VERSION 5.8 ;
BUSBITCHARS "[]" ;
DIVIDERCHAR "/" ;
UNITS
    DATABASE MICRONS 1000 ;
END UNITS

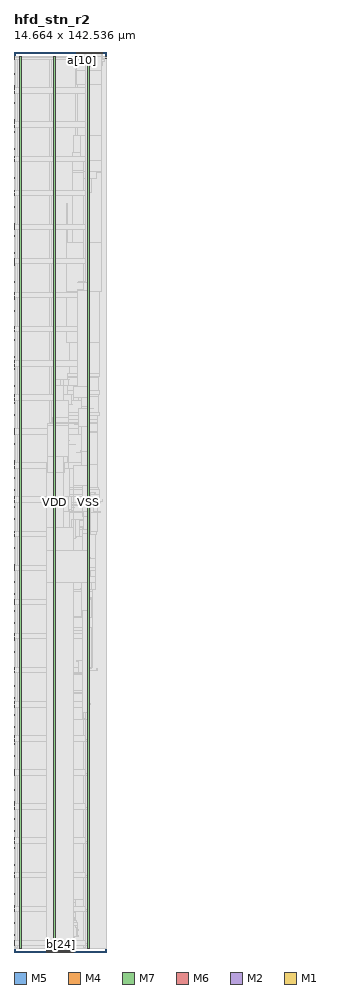
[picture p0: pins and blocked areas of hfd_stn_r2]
MACRO hfd_stn_r2
  FOREIGN hfd_stn_r2 0 0 ;
  CLASS BLOCK ;
  SIZE 14.664 BY 142.536 ;
  PIN a[0]
    DIRECTION INPUT ;
    USE SIGNAL ;
    PORT
      LAYER M5 ;
        RECT  9.84 142.344 9.864 142.536 ;
    END
  END a[0]
  PIN a[10]
    DIRECTION INPUT ;
    USE SIGNAL ;
    PORT
      LAYER M5 ;
        RECT  10.8 142.344 10.824 142.536 ;
    END
  END a[10]
  PIN a[11]
    DIRECTION INPUT ;
    USE SIGNAL ;
    PORT
      LAYER M5 ;
        RECT  10.896 142.344 10.92 142.536 ;
    END
  END a[11]
  PIN a[12]
    DIRECTION INPUT ;
    USE SIGNAL ;
    PORT
      LAYER M5 ;
        RECT  10.992 142.344 11.016 142.536 ;
    END
  END a[12]
  PIN a[13]
    DIRECTION INPUT ;
    USE SIGNAL ;
    PORT
      LAYER M5 ;
        RECT  11.088 142.344 11.112 142.536 ;
    END
  END a[13]
  PIN a[14]
    DIRECTION INPUT ;
    USE SIGNAL ;
    PORT
      LAYER M5 ;
        RECT  11.184 142.344 11.208 142.536 ;
    END
  END a[14]
  PIN a[15]
    DIRECTION INPUT ;
    USE SIGNAL ;
    PORT
      LAYER M5 ;
        RECT  11.28 142.344 11.304 142.536 ;
    END
  END a[15]
  PIN a[16]
    DIRECTION INPUT ;
    USE SIGNAL ;
    PORT
      LAYER M5 ;
        RECT  11.376 142.344 11.4 142.536 ;
    END
  END a[16]
  PIN a[17]
    DIRECTION INPUT ;
    USE SIGNAL ;
    PORT
      LAYER M5 ;
        RECT  11.472 142.344 11.496 142.536 ;
    END
  END a[17]
  PIN a[18]
    DIRECTION INPUT ;
    USE SIGNAL ;
    PORT
      LAYER M5 ;
        RECT  11.568 142.344 11.592 142.536 ;
    END
  END a[18]
  PIN a[19]
    DIRECTION INPUT ;
    USE SIGNAL ;
    PORT
      LAYER M5 ;
        RECT  11.664 142.344 11.688 142.536 ;
    END
  END a[19]
  PIN a[1]
    DIRECTION INPUT ;
    USE SIGNAL ;
    PORT
      LAYER M5 ;
        RECT  9.936 142.344 9.96 142.536 ;
    END
  END a[1]
  PIN a[20]
    DIRECTION INPUT ;
    USE SIGNAL ;
    PORT
      LAYER M5 ;
        RECT  11.76 142.344 11.784 142.536 ;
    END
  END a[20]
  PIN a[21]
    DIRECTION INPUT ;
    USE SIGNAL ;
    PORT
      LAYER M5 ;
        RECT  11.856 142.344 11.88 142.536 ;
    END
  END a[21]
  PIN a[22]
    DIRECTION INPUT ;
    USE SIGNAL ;
    PORT
      LAYER M5 ;
        RECT  11.952 142.344 11.976 142.536 ;
    END
  END a[22]
  PIN a[23]
    DIRECTION INPUT ;
    USE SIGNAL ;
    PORT
      LAYER M5 ;
        RECT  12.048 142.344 12.072 142.536 ;
    END
  END a[23]
  PIN a[24]
    DIRECTION INPUT ;
    USE SIGNAL ;
    PORT
      LAYER M5 ;
        RECT  12.144 142.344 12.168 142.536 ;
    END
  END a[24]
  PIN a[25]
    DIRECTION INPUT ;
    USE SIGNAL ;
    PORT
      LAYER M5 ;
        RECT  12.24 142.344 12.264 142.536 ;
    END
  END a[25]
  PIN a[26]
    DIRECTION INPUT ;
    USE SIGNAL ;
    PORT
      LAYER M5 ;
        RECT  12.336 142.344 12.36 142.536 ;
    END
  END a[26]
  PIN a[27]
    DIRECTION INPUT ;
    USE SIGNAL ;
    PORT
      LAYER M5 ;
        RECT  12.432 142.344 12.456 142.536 ;
    END
  END a[27]
  PIN a[28]
    DIRECTION INPUT ;
    USE SIGNAL ;
    PORT
      LAYER M5 ;
        RECT  12.528 142.344 12.552 142.536 ;
    END
  END a[28]
  PIN a[29]
    DIRECTION INPUT ;
    USE SIGNAL ;
    PORT
      LAYER M5 ;
        RECT  12.624 142.344 12.648 142.536 ;
    END
  END a[29]
  PIN a[2]
    DIRECTION INPUT ;
    USE SIGNAL ;
    PORT
      LAYER M5 ;
        RECT  10.032 142.344 10.056 142.536 ;
    END
  END a[2]
  PIN a[30]
    DIRECTION INPUT ;
    USE SIGNAL ;
    PORT
      LAYER M5 ;
        RECT  12.72 142.344 12.744 142.536 ;
    END
  END a[30]
  PIN a[31]
    DIRECTION INPUT ;
    USE SIGNAL ;
    PORT
      LAYER M5 ;
        RECT  12.816 142.344 12.84 142.536 ;
    END
  END a[31]
  PIN a[32]
    DIRECTION INPUT ;
    USE SIGNAL ;
    PORT
      LAYER M5 ;
        RECT  12.912 142.344 12.936 142.536 ;
    END
  END a[32]
  PIN a[33]
    DIRECTION INPUT ;
    USE SIGNAL ;
    PORT
      LAYER M5 ;
        RECT  13.008 142.344 13.032 142.536 ;
    END
  END a[33]
  PIN a[34]
    DIRECTION INPUT ;
    USE SIGNAL ;
    PORT
      LAYER M5 ;
        RECT  13.104 142.344 13.128 142.536 ;
    END
  END a[34]
  PIN a[35]
    DIRECTION INPUT ;
    USE SIGNAL ;
    PORT
      LAYER M5 ;
        RECT  13.2 142.344 13.224 142.536 ;
    END
  END a[35]
  PIN a[36]
    DIRECTION INPUT ;
    USE SIGNAL ;
    PORT
      LAYER M5 ;
        RECT  13.296 142.344 13.32 142.536 ;
    END
  END a[36]
  PIN a[37]
    DIRECTION INPUT ;
    USE SIGNAL ;
    PORT
      LAYER M5 ;
        RECT  13.392 142.344 13.416 142.536 ;
    END
  END a[37]
  PIN a[38]
    DIRECTION INPUT ;
    USE SIGNAL ;
    PORT
      LAYER M5 ;
        RECT  13.488 142.344 13.512 142.536 ;
    END
  END a[38]
  PIN a[39]
    DIRECTION INPUT ;
    USE SIGNAL ;
    PORT
      LAYER M5 ;
        RECT  13.584 142.344 13.608 142.536 ;
    END
  END a[39]
  PIN a[3]
    DIRECTION INPUT ;
    USE SIGNAL ;
    PORT
      LAYER M5 ;
        RECT  10.128 142.344 10.152 142.536 ;
    END
  END a[3]
  PIN a[40]
    DIRECTION INPUT ;
    USE SIGNAL ;
    PORT
      LAYER M5 ;
        RECT  13.68 142.344 13.704 142.536 ;
    END
  END a[40]
  PIN a[41]
    DIRECTION INPUT ;
    USE SIGNAL ;
    PORT
      LAYER M5 ;
        RECT  13.776 142.344 13.8 142.536 ;
    END
  END a[41]
  PIN a[42]
    DIRECTION INPUT ;
    USE SIGNAL ;
    PORT
      LAYER M5 ;
        RECT  13.872 142.344 13.896 142.536 ;
    END
  END a[42]
  PIN a[43]
    DIRECTION OUTPUT ;
    USE SIGNAL ;
    PORT
      LAYER M5 ;
        RECT  13.968 142.344 13.992 142.536 ;
    END
  END a[43]
  PIN a[4]
    DIRECTION INPUT ;
    USE SIGNAL ;
    PORT
      LAYER M5 ;
        RECT  10.224 142.344 10.248 142.536 ;
    END
  END a[4]
  PIN a[5]
    DIRECTION INPUT ;
    USE SIGNAL ;
    PORT
      LAYER M5 ;
        RECT  10.32 142.344 10.344 142.536 ;
    END
  END a[5]
  PIN a[6]
    DIRECTION INPUT ;
    USE SIGNAL ;
    PORT
      LAYER M5 ;
        RECT  10.416 142.344 10.44 142.536 ;
    END
  END a[6]
  PIN a[7]
    DIRECTION INPUT ;
    USE SIGNAL ;
    PORT
      LAYER M5 ;
        RECT  10.512 142.344 10.536 142.536 ;
    END
  END a[7]
  PIN a[8]
    DIRECTION INPUT ;
    USE SIGNAL ;
    PORT
      LAYER M5 ;
        RECT  10.608 142.344 10.632 142.536 ;
    END
  END a[8]
  PIN a[9]
    DIRECTION INPUT ;
    USE SIGNAL ;
    PORT
      LAYER M5 ;
        RECT  10.704 142.344 10.728 142.536 ;
    END
  END a[9]
  PIN b[0]
    DIRECTION OUTPUT ;
    USE SIGNAL ;
    PORT
      LAYER M5 ;
        RECT  5.184 0 5.208 0.192 ;
    END
  END b[0]
  PIN b[10]
    DIRECTION OUTPUT ;
    USE SIGNAL ;
    PORT
      LAYER M5 ;
        RECT  6.144 0 6.168 0.192 ;
    END
  END b[10]
  PIN b[11]
    DIRECTION OUTPUT ;
    USE SIGNAL ;
    PORT
      LAYER M5 ;
        RECT  6.24 0 6.264 0.192 ;
    END
  END b[11]
  PIN b[12]
    DIRECTION OUTPUT ;
    USE SIGNAL ;
    PORT
      LAYER M5 ;
        RECT  6.336 0 6.36 0.192 ;
    END
  END b[12]
  PIN b[13]
    DIRECTION OUTPUT ;
    USE SIGNAL ;
    PORT
      LAYER M5 ;
        RECT  6.432 0 6.456 0.192 ;
    END
  END b[13]
  PIN b[14]
    DIRECTION OUTPUT ;
    USE SIGNAL ;
    PORT
      LAYER M5 ;
        RECT  6.528 0 6.552 0.192 ;
    END
  END b[14]
  PIN b[15]
    DIRECTION OUTPUT ;
    USE SIGNAL ;
    PORT
      LAYER M5 ;
        RECT  6.624 0 6.648 0.192 ;
    END
  END b[15]
  PIN b[16]
    DIRECTION OUTPUT ;
    USE SIGNAL ;
    PORT
      LAYER M5 ;
        RECT  6.72 0 6.744 0.192 ;
    END
  END b[16]
  PIN b[17]
    DIRECTION OUTPUT ;
    USE SIGNAL ;
    PORT
      LAYER M5 ;
        RECT  6.816 0 6.84 0.192 ;
    END
  END b[17]
  PIN b[18]
    DIRECTION OUTPUT ;
    USE SIGNAL ;
    PORT
      LAYER M5 ;
        RECT  6.912 0 6.936 0.192 ;
    END
  END b[18]
  PIN b[19]
    DIRECTION OUTPUT ;
    USE SIGNAL ;
    PORT
      LAYER M5 ;
        RECT  7.008 0 7.032 0.192 ;
    END
  END b[19]
  PIN b[1]
    DIRECTION OUTPUT ;
    USE SIGNAL ;
    PORT
      LAYER M5 ;
        RECT  5.28 0 5.304 0.192 ;
    END
  END b[1]
  PIN b[20]
    DIRECTION OUTPUT ;
    USE SIGNAL ;
    PORT
      LAYER M5 ;
        RECT  7.104 0 7.128 0.192 ;
    END
  END b[20]
  PIN b[21]
    DIRECTION OUTPUT ;
    USE SIGNAL ;
    PORT
      LAYER M5 ;
        RECT  7.2 0 7.224 0.192 ;
    END
  END b[21]
  PIN b[22]
    DIRECTION OUTPUT ;
    USE SIGNAL ;
    PORT
      LAYER M5 ;
        RECT  7.296 0 7.32 0.192 ;
    END
  END b[22]
  PIN b[23]
    DIRECTION OUTPUT ;
    USE SIGNAL ;
    PORT
      LAYER M5 ;
        RECT  7.392 0 7.416 0.192 ;
    END
  END b[23]
  PIN b[24]
    DIRECTION OUTPUT ;
    USE SIGNAL ;
    PORT
      LAYER M5 ;
        RECT  7.488 0 7.512 0.192 ;
    END
  END b[24]
  PIN b[25]
    DIRECTION OUTPUT ;
    USE SIGNAL ;
    PORT
      LAYER M5 ;
        RECT  7.584 0 7.608 0.192 ;
    END
  END b[25]
  PIN b[26]
    DIRECTION OUTPUT ;
    USE SIGNAL ;
    PORT
      LAYER M5 ;
        RECT  7.68 0 7.704 0.192 ;
    END
  END b[26]
  PIN b[27]
    DIRECTION OUTPUT ;
    USE SIGNAL ;
    PORT
      LAYER M5 ;
        RECT  7.776 0 7.8 0.192 ;
    END
  END b[27]
  PIN b[28]
    DIRECTION OUTPUT ;
    USE SIGNAL ;
    PORT
      LAYER M5 ;
        RECT  7.872 0 7.896 0.192 ;
    END
  END b[28]
  PIN b[29]
    DIRECTION OUTPUT ;
    USE SIGNAL ;
    PORT
      LAYER M5 ;
        RECT  7.968 0 7.992 0.192 ;
    END
  END b[29]
  PIN b[2]
    DIRECTION OUTPUT ;
    USE SIGNAL ;
    PORT
      LAYER M5 ;
        RECT  5.376 0 5.4 0.192 ;
    END
  END b[2]
  PIN b[30]
    DIRECTION OUTPUT ;
    USE SIGNAL ;
    PORT
      LAYER M5 ;
        RECT  8.064 0 8.088 0.192 ;
    END
  END b[30]
  PIN b[31]
    DIRECTION OUTPUT ;
    USE SIGNAL ;
    PORT
      LAYER M5 ;
        RECT  8.16 0 8.184 0.192 ;
    END
  END b[31]
  PIN b[32]
    DIRECTION OUTPUT ;
    USE SIGNAL ;
    PORT
      LAYER M5 ;
        RECT  8.256 0 8.28 0.192 ;
    END
  END b[32]
  PIN b[33]
    DIRECTION OUTPUT ;
    USE SIGNAL ;
    PORT
      LAYER M5 ;
        RECT  8.352 0 8.376 0.192 ;
    END
  END b[33]
  PIN b[34]
    DIRECTION OUTPUT ;
    USE SIGNAL ;
    PORT
      LAYER M5 ;
        RECT  8.448 0 8.472 0.192 ;
    END
  END b[34]
  PIN b[35]
    DIRECTION OUTPUT ;
    USE SIGNAL ;
    PORT
      LAYER M5 ;
        RECT  8.544 0 8.568 0.192 ;
    END
  END b[35]
  PIN b[36]
    DIRECTION OUTPUT ;
    USE SIGNAL ;
    PORT
      LAYER M5 ;
        RECT  8.64 0 8.664 0.192 ;
    END
  END b[36]
  PIN b[37]
    DIRECTION OUTPUT ;
    USE SIGNAL ;
    PORT
      LAYER M5 ;
        RECT  8.736 0 8.76 0.192 ;
    END
  END b[37]
  PIN b[38]
    DIRECTION OUTPUT ;
    USE SIGNAL ;
    PORT
      LAYER M5 ;
        RECT  8.832 0 8.856 0.192 ;
    END
  END b[38]
  PIN b[39]
    DIRECTION OUTPUT ;
    USE SIGNAL ;
    PORT
      LAYER M5 ;
        RECT  8.928 0 8.952 0.192 ;
    END
  END b[39]
  PIN b[3]
    DIRECTION OUTPUT ;
    USE SIGNAL ;
    PORT
      LAYER M5 ;
        RECT  5.472 0 5.496 0.192 ;
    END
  END b[3]
  PIN b[40]
    DIRECTION OUTPUT ;
    USE SIGNAL ;
    PORT
      LAYER M5 ;
        RECT  9.024 0 9.048 0.192 ;
    END
  END b[40]
  PIN b[41]
    DIRECTION OUTPUT ;
    USE SIGNAL ;
    PORT
      LAYER M5 ;
        RECT  9.12 0 9.144 0.192 ;
    END
  END b[41]
  PIN b[42]
    DIRECTION OUTPUT ;
    USE SIGNAL ;
    PORT
      LAYER M5 ;
        RECT  9.216 0 9.24 0.192 ;
    END
  END b[42]
  PIN b[43]
    DIRECTION OUTPUT ;
    USE SIGNAL ;
    PORT
      LAYER M5 ;
        RECT  9.312 0 9.336 0.192 ;
    END
  END b[43]
  PIN b[44]
    DIRECTION OUTPUT ;
    USE SIGNAL ;
    PORT
      LAYER M5 ;
        RECT  9.408 0 9.432 0.192 ;
    END
  END b[44]
  PIN b[4]
    DIRECTION OUTPUT ;
    USE SIGNAL ;
    PORT
      LAYER M5 ;
        RECT  5.568 0 5.592 0.192 ;
    END
  END b[4]
  PIN b[5]
    DIRECTION OUTPUT ;
    USE SIGNAL ;
    PORT
      LAYER M5 ;
        RECT  5.664 0 5.688 0.192 ;
    END
  END b[5]
  PIN b[6]
    DIRECTION OUTPUT ;
    USE SIGNAL ;
    PORT
      LAYER M5 ;
        RECT  5.76 0 5.784 0.192 ;
    END
  END b[6]
  PIN b[7]
    DIRECTION OUTPUT ;
    USE SIGNAL ;
    PORT
      LAYER M5 ;
        RECT  5.856 0 5.88 0.192 ;
    END
  END b[7]
  PIN b[8]
    DIRECTION OUTPUT ;
    USE SIGNAL ;
    PORT
      LAYER M5 ;
        RECT  5.952 0 5.976 0.192 ;
    END
  END b[8]
  PIN b[9]
    DIRECTION OUTPUT ;
    USE SIGNAL ;
    PORT
      LAYER M5 ;
        RECT  6.048 0 6.072 0.192 ;
    END
  END b[9]
  PIN ck[0]
    DIRECTION INPUT ;
    USE SIGNAL ;
    PORT
      LAYER M4 ;
        RECT  14.472 141.552 14.664 141.576 ;
    END
  END ck[0]
  PIN rst[0]
    DIRECTION INPUT ;
    USE SIGNAL ;
    PORT
      LAYER M4 ;
        RECT  14.472 141.84 14.664 141.864 ;
    END
  END rst[0]
  PIN VDD
    DIRECTION INOUT ;
    USE POWER ;
    PORT
      LAYER M7 ;
        RECT  6.256 0.531 6.544 141.759 ;
      LAYER M6 ;
        RECT  0 136.572 0.032 136.86 ;
        RECT  0 131.172 0.032 131.46 ;
        RECT  0 125.772 0.032 126.06 ;
        RECT  0 120.372 0.032 120.66 ;
        RECT  0 114.972 0.032 115.26 ;
        RECT  0 109.572 0.032 109.86 ;
        RECT  0 104.172 0.032 104.46 ;
        RECT  0 98.772 0.032 99.06 ;
        RECT  0 93.372 0.032 93.66 ;
        RECT  0 87.972 0.032 88.26 ;
        RECT  0 82.572 0.032 82.86 ;
        RECT  0 77.172 0.032 77.46 ;
        RECT  0 71.772 0.032 72.06 ;
        RECT  0 66.372 0.032 66.66 ;
        RECT  0 60.972 0.032 61.26 ;
        RECT  0 55.572 0.032 55.86 ;
        RECT  0 50.172 0.032 50.46 ;
        RECT  0 44.772 0.032 45.06 ;
        RECT  0 39.372 0.032 39.66 ;
        RECT  0 33.972 0.032 34.26 ;
        RECT  0 28.572 0.032 28.86 ;
        RECT  0 23.172 0.032 23.46 ;
        RECT  0 17.772 0.032 18.06 ;
        RECT  0 12.372 0.032 12.66 ;
        RECT  0 6.972 0.032 7.26 ;
        RECT  0 1.572 0.032 1.86 ;
      LAYER M2 ;
        RECT  0 141.741 0.018 141.759 ;
        RECT  0 141.201 0.018 141.219 ;
        RECT  0 140.661 0.018 140.679 ;
        RECT  0 140.121 0.018 140.139 ;
        RECT  0 139.581 0.018 139.599 ;
        RECT  0 139.041 0.018 139.059 ;
        RECT  0 138.501 0.018 138.519 ;
        RECT  0 137.961 0.018 137.979 ;
        RECT  0 137.421 0.018 137.439 ;
        RECT  0 136.881 0.018 136.899 ;
        RECT  0 136.341 0.018 136.359 ;
        RECT  0 135.801 0.018 135.819 ;
        RECT  0 135.261 0.018 135.279 ;
        RECT  0 134.721 0.018 134.739 ;
        RECT  0 134.181 0.018 134.199 ;
        RECT  0 133.641 0.018 133.659 ;
        RECT  0 133.101 0.018 133.119 ;
        RECT  0 132.561 0.018 132.579 ;
        RECT  0 132.021 0.018 132.039 ;
        RECT  0 131.481 0.018 131.499 ;
        RECT  0 130.941 0.018 130.959 ;
        RECT  0 130.401 0.018 130.419 ;
        RECT  0 129.861 0.018 129.879 ;
        RECT  0 129.321 0.018 129.339 ;
        RECT  0 128.781 0.018 128.799 ;
        RECT  0 128.241 0.018 128.259 ;
        RECT  0 127.701 0.018 127.719 ;
        RECT  0 127.161 0.018 127.179 ;
        RECT  0 126.621 0.018 126.639 ;
        RECT  0 126.081 0.018 126.099 ;
        RECT  0 125.541 0.018 125.559 ;
        RECT  0 125.001 0.018 125.019 ;
        RECT  0 124.461 0.018 124.479 ;
        RECT  0 123.921 0.018 123.939 ;
        RECT  0 123.381 0.018 123.399 ;
        RECT  0 122.841 0.018 122.859 ;
        RECT  0 122.301 0.018 122.319 ;
        RECT  0 121.761 0.018 121.779 ;
        RECT  0 121.221 0.018 121.239 ;
        RECT  0 120.681 0.018 120.699 ;
        RECT  0 120.141 0.018 120.159 ;
        RECT  0 119.601 0.018 119.619 ;
        RECT  0 119.061 0.018 119.079 ;
        RECT  0 118.521 0.018 118.539 ;
        RECT  0 117.981 0.018 117.999 ;
        RECT  0 117.441 0.018 117.459 ;
        RECT  0 116.901 0.018 116.919 ;
        RECT  0 116.361 0.018 116.379 ;
        RECT  0 115.821 0.018 115.839 ;
        RECT  0 115.281 0.018 115.299 ;
        RECT  0 114.741 0.018 114.759 ;
        RECT  0 114.201 0.018 114.219 ;
        RECT  0 113.661 0.018 113.679 ;
        RECT  0 113.121 0.018 113.139 ;
        RECT  0 112.581 0.018 112.599 ;
        RECT  0 112.041 0.018 112.059 ;
        RECT  0 111.501 0.018 111.519 ;
        RECT  0 110.961 0.018 110.979 ;
        RECT  0 110.421 0.018 110.439 ;
        RECT  0 109.881 0.018 109.899 ;
        RECT  0 109.341 0.018 109.359 ;
        RECT  0 108.801 0.018 108.819 ;
        RECT  0 108.261 0.018 108.279 ;
        RECT  0 107.721 0.018 107.739 ;
        RECT  0 107.181 0.018 107.199 ;
        RECT  0 106.641 0.018 106.659 ;
        RECT  0 106.101 0.018 106.119 ;
        RECT  0 105.561 0.018 105.579 ;
        RECT  0 105.021 0.018 105.039 ;
        RECT  0 104.481 0.018 104.499 ;
        RECT  0 103.941 0.018 103.959 ;
        RECT  0 103.401 0.018 103.419 ;
        RECT  0 102.861 0.018 102.879 ;
        RECT  0 102.321 0.018 102.339 ;
        RECT  0 101.781 0.018 101.799 ;
        RECT  0 101.241 0.018 101.259 ;
        RECT  0 100.701 0.018 100.719 ;
        RECT  0 100.161 0.018 100.179 ;
        RECT  0 99.621 0.018 99.639 ;
        RECT  0 99.081 0.018 99.099 ;
        RECT  0 98.541 0.018 98.559 ;
        RECT  0 98.001 0.018 98.019 ;
        RECT  0 97.461 0.018 97.479 ;
        RECT  0 96.921 0.018 96.939 ;
        RECT  0 96.381 0.018 96.399 ;
        RECT  0 95.841 0.018 95.859 ;
        RECT  0 95.301 0.018 95.319 ;
        RECT  0 94.761 0.018 94.779 ;
        RECT  0 94.221 0.018 94.239 ;
        RECT  0 93.681 0.018 93.699 ;
        RECT  0 93.141 0.018 93.159 ;
        RECT  0 92.601 0.018 92.619 ;
        RECT  0 92.061 0.018 92.079 ;
        RECT  0 91.521 0.018 91.539 ;
        RECT  0 90.981 0.018 90.999 ;
        RECT  0 90.441 0.018 90.459 ;
        RECT  0 89.901 0.018 89.919 ;
        RECT  0 89.361 0.018 89.379 ;
        RECT  0 88.821 0.018 88.839 ;
        RECT  0 88.281 0.018 88.299 ;
        RECT  0 87.741 0.018 87.759 ;
        RECT  0 87.201 0.018 87.219 ;
        RECT  0 86.661 0.018 86.679 ;
        RECT  0 86.121 0.018 86.139 ;
        RECT  0 85.581 0.018 85.599 ;
        RECT  0 85.041 0.018 85.059 ;
        RECT  0 84.501 0.018 84.519 ;
        RECT  0 83.961 0.018 83.979 ;
        RECT  0 83.421 0.018 83.439 ;
        RECT  0 82.881 0.018 82.899 ;
        RECT  0 82.341 0.018 82.359 ;
        RECT  0 81.801 0.018 81.819 ;
        RECT  0 81.261 0.018 81.279 ;
        RECT  0 80.721 0.018 80.739 ;
        RECT  0 80.181 0.018 80.199 ;
        RECT  0 79.641 0.018 79.659 ;
        RECT  0 79.101 0.018 79.119 ;
        RECT  0 78.561 0.018 78.579 ;
        RECT  0 78.021 0.018 78.039 ;
        RECT  0 77.481 0.018 77.499 ;
        RECT  0 76.941 0.018 76.959 ;
        RECT  0 76.401 0.018 76.419 ;
        RECT  0 75.861 0.018 75.879 ;
        RECT  0 75.321 0.018 75.339 ;
        RECT  0 74.781 0.018 74.799 ;
        RECT  0 74.241 0.018 74.259 ;
        RECT  0 73.701 0.018 73.719 ;
        RECT  0 73.161 0.018 73.179 ;
        RECT  0 72.621 0.018 72.639 ;
        RECT  0 72.081 0.018 72.099 ;
        RECT  0 71.541 0.018 71.559 ;
        RECT  0 71.001 0.018 71.019 ;
        RECT  0 70.461 0.018 70.479 ;
        RECT  0 69.921 0.018 69.939 ;
        RECT  0 69.381 0.018 69.399 ;
        RECT  0 68.841 0.018 68.859 ;
        RECT  0 68.301 0.018 68.319 ;
        RECT  0 67.761 0.018 67.779 ;
        RECT  0 67.221 0.018 67.239 ;
        RECT  0 66.681 0.018 66.699 ;
        RECT  0 66.141 0.018 66.159 ;
        RECT  0 65.601 0.018 65.619 ;
        RECT  0 65.061 0.018 65.079 ;
        RECT  0 64.521 0.018 64.539 ;
        RECT  0 63.981 0.018 63.999 ;
        RECT  0 63.441 0.018 63.459 ;
        RECT  0 62.901 0.018 62.919 ;
        RECT  0 62.361 0.018 62.379 ;
        RECT  0 61.821 0.018 61.839 ;
        RECT  0 61.281 0.018 61.299 ;
        RECT  0 60.741 0.018 60.759 ;
        RECT  0 60.201 0.018 60.219 ;
        RECT  0 59.661 0.018 59.679 ;
        RECT  0 59.121 0.018 59.139 ;
        RECT  0 58.581 0.018 58.599 ;
        RECT  0 58.041 0.018 58.059 ;
        RECT  0 57.501 0.018 57.519 ;
        RECT  0 56.961 0.018 56.979 ;
        RECT  0 56.421 0.018 56.439 ;
        RECT  0 55.881 0.018 55.899 ;
        RECT  0 55.341 0.018 55.359 ;
        RECT  0 54.801 0.018 54.819 ;
        RECT  0 54.261 0.018 54.279 ;
        RECT  0 53.721 0.018 53.739 ;
        RECT  0 53.181 0.018 53.199 ;
        RECT  0 52.641 0.018 52.659 ;
        RECT  0 52.101 0.018 52.119 ;
        RECT  0 51.561 0.018 51.579 ;
        RECT  0 51.021 0.018 51.039 ;
        RECT  0 50.481 0.018 50.499 ;
        RECT  0 49.941 0.018 49.959 ;
        RECT  0 49.401 0.018 49.419 ;
        RECT  0 48.861 0.018 48.879 ;
        RECT  0 48.321 0.018 48.339 ;
        RECT  0 47.781 0.018 47.799 ;
        RECT  0 47.241 0.018 47.259 ;
        RECT  0 46.701 0.018 46.719 ;
        RECT  0 46.161 0.018 46.179 ;
        RECT  0 45.621 0.018 45.639 ;
        RECT  0 45.081 0.018 45.099 ;
        RECT  0 44.541 0.018 44.559 ;
        RECT  0 44.001 0.018 44.019 ;
        RECT  0 43.461 0.018 43.479 ;
        RECT  0 42.921 0.018 42.939 ;
        RECT  0 42.381 0.018 42.399 ;
        RECT  0 41.841 0.018 41.859 ;
        RECT  0 41.301 0.018 41.319 ;
        RECT  0 40.761 0.018 40.779 ;
        RECT  0 40.221 0.018 40.239 ;
        RECT  0 39.681 0.018 39.699 ;
        RECT  0 39.141 0.018 39.159 ;
        RECT  0 38.601 0.018 38.619 ;
        RECT  0 38.061 0.018 38.079 ;
        RECT  0 37.521 0.018 37.539 ;
        RECT  0 36.981 0.018 36.999 ;
        RECT  0 36.441 0.018 36.459 ;
        RECT  0 35.901 0.018 35.919 ;
        RECT  0 35.361 0.018 35.379 ;
        RECT  0 34.821 0.018 34.839 ;
        RECT  0 34.281 0.018 34.299 ;
        RECT  0 33.741 0.018 33.759 ;
        RECT  0 33.201 0.018 33.219 ;
        RECT  0 32.661 0.018 32.679 ;
        RECT  0 32.121 0.018 32.139 ;
        RECT  0 31.581 0.018 31.599 ;
        RECT  0 31.041 0.018 31.059 ;
        RECT  0 30.501 0.018 30.519 ;
        RECT  0 29.961 0.018 29.979 ;
        RECT  0 29.421 0.018 29.439 ;
        RECT  0 28.881 0.018 28.899 ;
        RECT  0 28.341 0.018 28.359 ;
        RECT  0 27.801 0.018 27.819 ;
        RECT  0 27.261 0.018 27.279 ;
        RECT  0 26.721 0.018 26.739 ;
        RECT  0 26.181 0.018 26.199 ;
        RECT  0 25.641 0.018 25.659 ;
        RECT  0 25.101 0.018 25.119 ;
        RECT  0 24.561 0.018 24.579 ;
        RECT  0 24.021 0.018 24.039 ;
        RECT  0 23.481 0.018 23.499 ;
        RECT  0 22.941 0.018 22.959 ;
        RECT  0 22.401 0.018 22.419 ;
        RECT  0 21.861 0.018 21.879 ;
        RECT  0 21.321 0.018 21.339 ;
        RECT  0 20.781 0.018 20.799 ;
        RECT  0 20.241 0.018 20.259 ;
        RECT  0 19.701 0.018 19.719 ;
        RECT  0 19.161 0.018 19.179 ;
        RECT  0 18.621 0.018 18.639 ;
        RECT  0 18.081 0.018 18.099 ;
        RECT  0 17.541 0.018 17.559 ;
        RECT  0 17.001 0.018 17.019 ;
        RECT  0 16.461 0.018 16.479 ;
        RECT  0 15.921 0.018 15.939 ;
        RECT  0 15.381 0.018 15.399 ;
        RECT  0 14.841 0.018 14.859 ;
        RECT  0 14.301 0.018 14.319 ;
        RECT  0 13.761 0.018 13.779 ;
        RECT  0 13.221 0.018 13.239 ;
        RECT  0 12.681 0.018 12.699 ;
        RECT  0 12.141 0.018 12.159 ;
        RECT  0 11.601 0.018 11.619 ;
        RECT  0 11.061 0.018 11.079 ;
        RECT  0 10.521 0.018 10.539 ;
        RECT  0 9.981 0.018 9.999 ;
        RECT  0 9.441 0.018 9.459 ;
        RECT  0 8.901 0.018 8.919 ;
        RECT  0 8.361 0.018 8.379 ;
        RECT  0 7.821 0.018 7.839 ;
        RECT  0 7.281 0.018 7.299 ;
        RECT  0 6.741 0.018 6.759 ;
        RECT  0 6.201 0.018 6.219 ;
        RECT  0 5.661 0.018 5.679 ;
        RECT  0 5.121 0.018 5.139 ;
        RECT  0 4.581 0.018 4.599 ;
        RECT  0 4.041 0.018 4.059 ;
        RECT  0 3.501 0.018 3.519 ;
        RECT  0 2.961 0.018 2.979 ;
        RECT  0 2.421 0.018 2.439 ;
        RECT  0 1.881 0.018 1.899 ;
        RECT  0 1.341 0.018 1.359 ;
        RECT  0 0.801 0.018 0.819 ;
      LAYER M1 ;
        RECT  0 141.741 0.018 141.759 ;
        RECT  0 141.201 0.018 141.219 ;
        RECT  0 140.661 0.018 140.679 ;
        RECT  0 140.121 0.018 140.139 ;
        RECT  0 139.581 0.018 139.599 ;
        RECT  0 139.041 0.018 139.059 ;
        RECT  0 138.501 0.018 138.519 ;
        RECT  0 137.961 0.018 137.979 ;
        RECT  0 137.421 0.018 137.439 ;
        RECT  0 136.881 0.018 136.899 ;
        RECT  0 136.341 0.018 136.359 ;
        RECT  0 135.801 0.018 135.819 ;
        RECT  0 135.261 0.018 135.279 ;
        RECT  0 134.721 0.018 134.739 ;
        RECT  0 134.181 0.018 134.199 ;
        RECT  0 133.641 0.018 133.659 ;
        RECT  0 133.101 0.018 133.119 ;
        RECT  0 132.561 0.018 132.579 ;
        RECT  0 132.021 0.018 132.039 ;
        RECT  0 131.481 0.018 131.499 ;
        RECT  0 130.941 0.018 130.959 ;
        RECT  0 130.401 0.018 130.419 ;
        RECT  0 129.861 0.018 129.879 ;
        RECT  0 129.321 0.018 129.339 ;
        RECT  0 128.781 0.018 128.799 ;
        RECT  0 128.241 0.018 128.259 ;
        RECT  0 127.701 0.018 127.719 ;
        RECT  0 127.161 0.018 127.179 ;
        RECT  0 126.621 0.018 126.639 ;
        RECT  0 126.081 0.018 126.099 ;
        RECT  0 125.541 0.018 125.559 ;
        RECT  0 125.001 0.018 125.019 ;
        RECT  0 124.461 0.018 124.479 ;
        RECT  0 123.921 0.018 123.939 ;
        RECT  0 123.381 0.018 123.399 ;
        RECT  0 122.841 0.018 122.859 ;
        RECT  0 122.301 0.018 122.319 ;
        RECT  0 121.761 0.018 121.779 ;
        RECT  0 121.221 0.018 121.239 ;
        RECT  0 120.681 0.018 120.699 ;
        RECT  0 120.141 0.018 120.159 ;
        RECT  0 119.601 0.018 119.619 ;
        RECT  0 119.061 0.018 119.079 ;
        RECT  0 118.521 0.018 118.539 ;
        RECT  0 117.981 0.018 117.999 ;
        RECT  0 117.441 0.018 117.459 ;
        RECT  0 116.901 0.018 116.919 ;
        RECT  0 116.361 0.018 116.379 ;
        RECT  0 115.821 0.018 115.839 ;
        RECT  0 115.281 0.018 115.299 ;
        RECT  0 114.741 0.018 114.759 ;
        RECT  0 114.201 0.018 114.219 ;
        RECT  0 113.661 0.018 113.679 ;
        RECT  0 113.121 0.018 113.139 ;
        RECT  0 112.581 0.018 112.599 ;
        RECT  0 112.041 0.018 112.059 ;
        RECT  0 111.501 0.018 111.519 ;
        RECT  0 110.961 0.018 110.979 ;
        RECT  0 110.421 0.018 110.439 ;
        RECT  0 109.881 0.018 109.899 ;
        RECT  0 109.341 0.018 109.359 ;
        RECT  0 108.801 0.018 108.819 ;
        RECT  0 108.261 0.018 108.279 ;
        RECT  0 107.721 0.018 107.739 ;
        RECT  0 107.181 0.018 107.199 ;
        RECT  0 106.641 0.018 106.659 ;
        RECT  0 106.101 0.018 106.119 ;
        RECT  0 105.561 0.018 105.579 ;
        RECT  0 105.021 0.018 105.039 ;
        RECT  0 104.481 0.018 104.499 ;
        RECT  0 103.941 0.018 103.959 ;
        RECT  0 103.401 0.018 103.419 ;
        RECT  0 102.861 0.018 102.879 ;
        RECT  0 102.321 0.018 102.339 ;
        RECT  0 101.781 0.018 101.799 ;
        RECT  0 101.241 0.018 101.259 ;
        RECT  0 100.701 0.018 100.719 ;
        RECT  0 100.161 0.018 100.179 ;
        RECT  0 99.621 0.018 99.639 ;
        RECT  0 99.081 0.018 99.099 ;
        RECT  0 98.541 0.018 98.559 ;
        RECT  0 98.001 0.018 98.019 ;
        RECT  0 97.461 0.018 97.479 ;
        RECT  0 96.921 0.018 96.939 ;
        RECT  0 96.381 0.018 96.399 ;
        RECT  0 95.841 0.018 95.859 ;
        RECT  0 95.301 0.018 95.319 ;
        RECT  0 94.761 0.018 94.779 ;
        RECT  0 94.221 0.018 94.239 ;
        RECT  0 93.681 0.018 93.699 ;
        RECT  0 93.141 0.018 93.159 ;
        RECT  0 92.601 0.018 92.619 ;
        RECT  0 92.061 0.018 92.079 ;
        RECT  0 91.521 0.018 91.539 ;
        RECT  0 90.981 0.018 90.999 ;
        RECT  0 90.441 0.018 90.459 ;
        RECT  0 89.901 0.018 89.919 ;
        RECT  0 89.361 0.018 89.379 ;
        RECT  0 88.821 0.018 88.839 ;
        RECT  0 88.281 0.018 88.299 ;
        RECT  0 87.741 0.018 87.759 ;
        RECT  0 87.201 0.018 87.219 ;
        RECT  0 86.661 0.018 86.679 ;
        RECT  0 86.121 0.018 86.139 ;
        RECT  0 85.581 0.018 85.599 ;
        RECT  0 85.041 0.018 85.059 ;
        RECT  0 84.501 0.018 84.519 ;
        RECT  0 83.961 0.018 83.979 ;
        RECT  0 83.421 0.018 83.439 ;
        RECT  0 82.881 0.018 82.899 ;
        RECT  0 82.341 0.018 82.359 ;
        RECT  0 81.801 0.018 81.819 ;
        RECT  0 81.261 0.018 81.279 ;
        RECT  0 80.721 0.018 80.739 ;
        RECT  0 80.181 0.018 80.199 ;
        RECT  0 79.641 0.018 79.659 ;
        RECT  0 79.101 0.018 79.119 ;
        RECT  0 78.561 0.018 78.579 ;
        RECT  0 78.021 0.018 78.039 ;
        RECT  0 77.481 0.018 77.499 ;
        RECT  0 76.941 0.018 76.959 ;
        RECT  0 76.401 0.018 76.419 ;
        RECT  0 75.861 0.018 75.879 ;
        RECT  0 75.321 0.018 75.339 ;
        RECT  0 74.781 0.018 74.799 ;
        RECT  0 74.241 0.018 74.259 ;
        RECT  0 73.701 0.018 73.719 ;
        RECT  0 73.161 0.018 73.179 ;
        RECT  0 72.621 0.018 72.639 ;
        RECT  0 72.081 0.018 72.099 ;
        RECT  0 71.541 0.018 71.559 ;
        RECT  0 71.001 0.018 71.019 ;
        RECT  0 70.461 0.018 70.479 ;
        RECT  0 69.921 0.018 69.939 ;
        RECT  0 69.381 0.018 69.399 ;
        RECT  0 68.841 0.018 68.859 ;
        RECT  0 68.301 0.018 68.319 ;
        RECT  0 67.761 0.018 67.779 ;
        RECT  0 67.221 0.018 67.239 ;
        RECT  0 66.681 0.018 66.699 ;
        RECT  0 66.141 0.018 66.159 ;
        RECT  0 65.601 0.018 65.619 ;
        RECT  0 65.061 0.018 65.079 ;
        RECT  0 64.521 0.018 64.539 ;
        RECT  0 63.981 0.018 63.999 ;
        RECT  0 63.441 0.018 63.459 ;
        RECT  0 62.901 0.018 62.919 ;
        RECT  0 62.361 0.018 62.379 ;
        RECT  0 61.821 0.018 61.839 ;
        RECT  0 61.281 0.018 61.299 ;
        RECT  0 60.741 0.018 60.759 ;
        RECT  0 60.201 0.018 60.219 ;
        RECT  0 59.661 0.018 59.679 ;
        RECT  0 59.121 0.018 59.139 ;
        RECT  0 58.581 0.018 58.599 ;
        RECT  0 58.041 0.018 58.059 ;
        RECT  0 57.501 0.018 57.519 ;
        RECT  0 56.961 0.018 56.979 ;
        RECT  0 56.421 0.018 56.439 ;
        RECT  0 55.881 0.018 55.899 ;
        RECT  0 55.341 0.018 55.359 ;
        RECT  0 54.801 0.018 54.819 ;
        RECT  0 54.261 0.018 54.279 ;
        RECT  0 53.721 0.018 53.739 ;
        RECT  0 53.181 0.018 53.199 ;
        RECT  0 52.641 0.018 52.659 ;
        RECT  0 52.101 0.018 52.119 ;
        RECT  0 51.561 0.018 51.579 ;
        RECT  0 51.021 0.018 51.039 ;
        RECT  0 50.481 0.018 50.499 ;
        RECT  0 49.941 0.018 49.959 ;
        RECT  0 49.401 0.018 49.419 ;
        RECT  0 48.861 0.018 48.879 ;
        RECT  0 48.321 0.018 48.339 ;
        RECT  0 47.781 0.018 47.799 ;
        RECT  0 47.241 0.018 47.259 ;
        RECT  0 46.701 0.018 46.719 ;
        RECT  0 46.161 0.018 46.179 ;
        RECT  0 45.621 0.018 45.639 ;
        RECT  0 45.081 0.018 45.099 ;
        RECT  0 44.541 0.018 44.559 ;
        RECT  0 44.001 0.018 44.019 ;
        RECT  0 43.461 0.018 43.479 ;
        RECT  0 42.921 0.018 42.939 ;
        RECT  0 42.381 0.018 42.399 ;
        RECT  0 41.841 0.018 41.859 ;
        RECT  0 41.301 0.018 41.319 ;
        RECT  0 40.761 0.018 40.779 ;
        RECT  0 40.221 0.018 40.239 ;
        RECT  0 39.681 0.018 39.699 ;
        RECT  0 39.141 0.018 39.159 ;
        RECT  0 38.601 0.018 38.619 ;
        RECT  0 38.061 0.018 38.079 ;
        RECT  0 37.521 0.018 37.539 ;
        RECT  0 36.981 0.018 36.999 ;
        RECT  0 36.441 0.018 36.459 ;
        RECT  0 35.901 0.018 35.919 ;
        RECT  0 35.361 0.018 35.379 ;
        RECT  0 34.821 0.018 34.839 ;
        RECT  0 34.281 0.018 34.299 ;
        RECT  0 33.741 0.018 33.759 ;
        RECT  0 33.201 0.018 33.219 ;
        RECT  0 32.661 0.018 32.679 ;
        RECT  0 32.121 0.018 32.139 ;
        RECT  0 31.581 0.018 31.599 ;
        RECT  0 31.041 0.018 31.059 ;
        RECT  0 30.501 0.018 30.519 ;
        RECT  0 29.961 0.018 29.979 ;
        RECT  0 29.421 0.018 29.439 ;
        RECT  0 28.881 0.018 28.899 ;
        RECT  0 28.341 0.018 28.359 ;
        RECT  0 27.801 0.018 27.819 ;
        RECT  0 27.261 0.018 27.279 ;
        RECT  0 26.721 0.018 26.739 ;
        RECT  0 26.181 0.018 26.199 ;
        RECT  0 25.641 0.018 25.659 ;
        RECT  0 25.101 0.018 25.119 ;
        RECT  0 24.561 0.018 24.579 ;
        RECT  0 24.021 0.018 24.039 ;
        RECT  0 23.481 0.018 23.499 ;
        RECT  0 22.941 0.018 22.959 ;
        RECT  0 22.401 0.018 22.419 ;
        RECT  0 21.861 0.018 21.879 ;
        RECT  0 21.321 0.018 21.339 ;
        RECT  0 20.781 0.018 20.799 ;
        RECT  0 20.241 0.018 20.259 ;
        RECT  0 19.701 0.018 19.719 ;
        RECT  0 19.161 0.018 19.179 ;
        RECT  0 18.621 0.018 18.639 ;
        RECT  0 18.081 0.018 18.099 ;
        RECT  0 17.541 0.018 17.559 ;
        RECT  0 17.001 0.018 17.019 ;
        RECT  0 16.461 0.018 16.479 ;
        RECT  0 15.921 0.018 15.939 ;
        RECT  0 15.381 0.018 15.399 ;
        RECT  0 14.841 0.018 14.859 ;
        RECT  0 14.301 0.018 14.319 ;
        RECT  0 13.761 0.018 13.779 ;
        RECT  0 13.221 0.018 13.239 ;
        RECT  0 12.681 0.018 12.699 ;
        RECT  0 12.141 0.018 12.159 ;
        RECT  0 11.601 0.018 11.619 ;
        RECT  0 11.061 0.018 11.079 ;
        RECT  0 10.521 0.018 10.539 ;
        RECT  0 9.981 0.018 9.999 ;
        RECT  0 9.441 0.018 9.459 ;
        RECT  0 8.901 0.018 8.919 ;
        RECT  0 8.361 0.018 8.379 ;
        RECT  0 7.821 0.018 7.839 ;
        RECT  0 7.281 0.018 7.299 ;
        RECT  0 6.741 0.018 6.759 ;
        RECT  0 6.201 0.018 6.219 ;
        RECT  0 5.661 0.018 5.679 ;
        RECT  0 5.121 0.018 5.139 ;
        RECT  0 4.581 0.018 4.599 ;
        RECT  0 4.041 0.018 4.059 ;
        RECT  0 3.501 0.018 3.519 ;
        RECT  0 2.961 0.018 2.979 ;
        RECT  0 2.421 0.018 2.439 ;
        RECT  0 1.881 0.018 1.899 ;
        RECT  0 1.341 0.018 1.359 ;
        RECT  0 0.801 0.018 0.819 ;
    END
  END VDD
  PIN VSS
    DIRECTION INOUT ;
    USE GROUND ;
    PORT
      LAYER M7 ;
        RECT  11.656 0.531 11.944 141.759 ;
        RECT  0.856 0.531 1.144 141.759 ;
      LAYER M6 ;
        RECT  0 141.396 0.032 141.684 ;
        RECT  0 135.996 0.032 136.284 ;
        RECT  0 130.596 0.032 130.884 ;
        RECT  0 125.196 0.032 125.484 ;
        RECT  0 119.796 0.032 120.084 ;
        RECT  0 114.396 0.032 114.684 ;
        RECT  0 108.996 0.032 109.284 ;
        RECT  0 103.596 0.032 103.884 ;
        RECT  0 98.196 0.032 98.484 ;
        RECT  0 92.796 0.032 93.084 ;
        RECT  0 87.396 0.032 87.684 ;
        RECT  0 81.996 0.032 82.284 ;
        RECT  0 76.596 0.032 76.884 ;
        RECT  0 71.196 0.032 71.484 ;
        RECT  0 65.796 0.032 66.084 ;
        RECT  0 60.396 0.032 60.684 ;
        RECT  0 54.996 0.032 55.284 ;
        RECT  0 49.596 0.032 49.884 ;
        RECT  0 44.196 0.032 44.484 ;
        RECT  0 38.796 0.032 39.084 ;
        RECT  0 33.396 0.032 33.684 ;
        RECT  0 27.996 0.032 28.284 ;
        RECT  0 22.596 0.032 22.884 ;
        RECT  0 17.196 0.032 17.484 ;
        RECT  0 11.796 0.032 12.084 ;
        RECT  0 6.396 0.032 6.684 ;
        RECT  0 0.996 0.032 1.284 ;
      LAYER M2 ;
        RECT  0 141.471 0.018 141.489 ;
        RECT  0 140.931 0.018 140.949 ;
        RECT  0 140.391 0.018 140.409 ;
        RECT  0 139.851 0.018 139.869 ;
        RECT  0 139.311 0.018 139.329 ;
        RECT  0 138.771 0.018 138.789 ;
        RECT  0 138.231 0.018 138.249 ;
        RECT  0 137.691 0.018 137.709 ;
        RECT  0 137.151 0.018 137.169 ;
        RECT  0 136.611 0.018 136.629 ;
        RECT  0 136.071 0.018 136.089 ;
        RECT  0 135.531 0.018 135.549 ;
        RECT  0 134.991 0.018 135.009 ;
        RECT  0 134.451 0.018 134.469 ;
        RECT  0 133.911 0.018 133.929 ;
        RECT  0 133.371 0.018 133.389 ;
        RECT  0 132.831 0.018 132.849 ;
        RECT  0 132.291 0.018 132.309 ;
        RECT  0 131.751 0.018 131.769 ;
        RECT  0 131.211 0.018 131.229 ;
        RECT  0 130.671 0.018 130.689 ;
        RECT  0 130.131 0.018 130.149 ;
        RECT  0 129.591 0.018 129.609 ;
        RECT  0 129.051 0.018 129.069 ;
        RECT  0 128.511 0.018 128.529 ;
        RECT  0 127.971 0.018 127.989 ;
        RECT  0 127.431 0.018 127.449 ;
        RECT  0 126.891 0.018 126.909 ;
        RECT  0 126.351 0.018 126.369 ;
        RECT  0 125.811 0.018 125.829 ;
        RECT  0 125.271 0.018 125.289 ;
        RECT  0 124.731 0.018 124.749 ;
        RECT  0 124.191 0.018 124.209 ;
        RECT  0 123.651 0.018 123.669 ;
        RECT  0 123.111 0.018 123.129 ;
        RECT  0 122.571 0.018 122.589 ;
        RECT  0 122.031 0.018 122.049 ;
        RECT  0 121.491 0.018 121.509 ;
        RECT  0 120.951 0.018 120.969 ;
        RECT  0 120.411 0.018 120.429 ;
        RECT  0 119.871 0.018 119.889 ;
        RECT  0 119.331 0.018 119.349 ;
        RECT  0 118.791 0.018 118.809 ;
        RECT  0 118.251 0.018 118.269 ;
        RECT  0 117.711 0.018 117.729 ;
        RECT  0 117.171 0.018 117.189 ;
        RECT  0 116.631 0.018 116.649 ;
        RECT  0 116.091 0.018 116.109 ;
        RECT  0 115.551 0.018 115.569 ;
        RECT  0 115.011 0.018 115.029 ;
        RECT  0 114.471 0.018 114.489 ;
        RECT  0 113.931 0.018 113.949 ;
        RECT  0 113.391 0.018 113.409 ;
        RECT  0 112.851 0.018 112.869 ;
        RECT  0 112.311 0.018 112.329 ;
        RECT  0 111.771 0.018 111.789 ;
        RECT  0 111.231 0.018 111.249 ;
        RECT  0 110.691 0.018 110.709 ;
        RECT  0 110.151 0.018 110.169 ;
        RECT  0 109.611 0.018 109.629 ;
        RECT  0 109.071 0.018 109.089 ;
        RECT  0 108.531 0.018 108.549 ;
        RECT  0 107.991 0.018 108.009 ;
        RECT  0 107.451 0.018 107.469 ;
        RECT  0 106.911 0.018 106.929 ;
        RECT  0 106.371 0.018 106.389 ;
        RECT  0 105.831 0.018 105.849 ;
        RECT  0 105.291 0.018 105.309 ;
        RECT  0 104.751 0.018 104.769 ;
        RECT  0 104.211 0.018 104.229 ;
        RECT  0 103.671 0.018 103.689 ;
        RECT  0 103.131 0.018 103.149 ;
        RECT  0 102.591 0.018 102.609 ;
        RECT  0 102.051 0.018 102.069 ;
        RECT  0 101.511 0.018 101.529 ;
        RECT  0 100.971 0.018 100.989 ;
        RECT  0 100.431 0.018 100.449 ;
        RECT  0 99.891 0.018 99.909 ;
        RECT  0 99.351 0.018 99.369 ;
        RECT  0 98.811 0.018 98.829 ;
        RECT  0 98.271 0.018 98.289 ;
        RECT  0 97.731 0.018 97.749 ;
        RECT  0 97.191 0.018 97.209 ;
        RECT  0 96.651 0.018 96.669 ;
        RECT  0 96.111 0.018 96.129 ;
        RECT  0 95.571 0.018 95.589 ;
        RECT  0 95.031 0.018 95.049 ;
        RECT  0 94.491 0.018 94.509 ;
        RECT  0 93.951 0.018 93.969 ;
        RECT  0 93.411 0.018 93.429 ;
        RECT  0 92.871 0.018 92.889 ;
        RECT  0 92.331 0.018 92.349 ;
        RECT  0 91.791 0.018 91.809 ;
        RECT  0 91.251 0.018 91.269 ;
        RECT  0 90.711 0.018 90.729 ;
        RECT  0 90.171 0.018 90.189 ;
        RECT  0 89.631 0.018 89.649 ;
        RECT  0 89.091 0.018 89.109 ;
        RECT  0 88.551 0.018 88.569 ;
        RECT  0 88.011 0.018 88.029 ;
        RECT  0 87.471 0.018 87.489 ;
        RECT  0 86.931 0.018 86.949 ;
        RECT  0 86.391 0.018 86.409 ;
        RECT  0 85.851 0.018 85.869 ;
        RECT  0 85.311 0.018 85.329 ;
        RECT  0 84.771 0.018 84.789 ;
        RECT  0 84.231 0.018 84.249 ;
        RECT  0 83.691 0.018 83.709 ;
        RECT  0 83.151 0.018 83.169 ;
        RECT  0 82.611 0.018 82.629 ;
        RECT  0 82.071 0.018 82.089 ;
        RECT  0 81.531 0.018 81.549 ;
        RECT  0 80.991 0.018 81.009 ;
        RECT  0 80.451 0.018 80.469 ;
        RECT  0 79.911 0.018 79.929 ;
        RECT  0 79.371 0.018 79.389 ;
        RECT  0 78.831 0.018 78.849 ;
        RECT  0 78.291 0.018 78.309 ;
        RECT  0 77.751 0.018 77.769 ;
        RECT  0 77.211 0.018 77.229 ;
        RECT  0 76.671 0.018 76.689 ;
        RECT  0 76.131 0.018 76.149 ;
        RECT  0 75.591 0.018 75.609 ;
        RECT  0 75.051 0.018 75.069 ;
        RECT  0 74.511 0.018 74.529 ;
        RECT  0 73.971 0.018 73.989 ;
        RECT  0 73.431 0.018 73.449 ;
        RECT  0 72.891 0.018 72.909 ;
        RECT  0 72.351 0.018 72.369 ;
        RECT  0 71.811 0.018 71.829 ;
        RECT  0 71.271 0.018 71.289 ;
        RECT  0 70.731 0.018 70.749 ;
        RECT  0 70.191 0.018 70.209 ;
        RECT  0 69.651 0.018 69.669 ;
        RECT  0 69.111 0.018 69.129 ;
        RECT  0 68.571 0.018 68.589 ;
        RECT  0 68.031 0.018 68.049 ;
        RECT  0 67.491 0.018 67.509 ;
        RECT  0 66.951 0.018 66.969 ;
        RECT  0 66.411 0.018 66.429 ;
        RECT  0 65.871 0.018 65.889 ;
        RECT  0 65.331 0.018 65.349 ;
        RECT  0 64.791 0.018 64.809 ;
        RECT  0 64.251 0.018 64.269 ;
        RECT  0 63.711 0.018 63.729 ;
        RECT  0 63.171 0.018 63.189 ;
        RECT  0 62.631 0.018 62.649 ;
        RECT  0 62.091 0.018 62.109 ;
        RECT  0 61.551 0.018 61.569 ;
        RECT  0 61.011 0.018 61.029 ;
        RECT  0 60.471 0.018 60.489 ;
        RECT  0 59.931 0.018 59.949 ;
        RECT  0 59.391 0.018 59.409 ;
        RECT  0 58.851 0.018 58.869 ;
        RECT  0 58.311 0.018 58.329 ;
        RECT  0 57.771 0.018 57.789 ;
        RECT  0 57.231 0.018 57.249 ;
        RECT  0 56.691 0.018 56.709 ;
        RECT  0 56.151 0.018 56.169 ;
        RECT  0 55.611 0.018 55.629 ;
        RECT  0 55.071 0.018 55.089 ;
        RECT  0 54.531 0.018 54.549 ;
        RECT  0 53.991 0.018 54.009 ;
        RECT  0 53.451 0.018 53.469 ;
        RECT  0 52.911 0.018 52.929 ;
        RECT  0 52.371 0.018 52.389 ;
        RECT  0 51.831 0.018 51.849 ;
        RECT  0 51.291 0.018 51.309 ;
        RECT  0 50.751 0.018 50.769 ;
        RECT  0 50.211 0.018 50.229 ;
        RECT  0 49.671 0.018 49.689 ;
        RECT  0 49.131 0.018 49.149 ;
        RECT  0 48.591 0.018 48.609 ;
        RECT  0 48.051 0.018 48.069 ;
        RECT  0 47.511 0.018 47.529 ;
        RECT  0 46.971 0.018 46.989 ;
        RECT  0 46.431 0.018 46.449 ;
        RECT  0 45.891 0.018 45.909 ;
        RECT  0 45.351 0.018 45.369 ;
        RECT  0 44.811 0.018 44.829 ;
        RECT  0 44.271 0.018 44.289 ;
        RECT  0 43.731 0.018 43.749 ;
        RECT  0 43.191 0.018 43.209 ;
        RECT  0 42.651 0.018 42.669 ;
        RECT  0 42.111 0.018 42.129 ;
        RECT  0 41.571 0.018 41.589 ;
        RECT  0 41.031 0.018 41.049 ;
        RECT  0 40.491 0.018 40.509 ;
        RECT  0 39.951 0.018 39.969 ;
        RECT  0 39.411 0.018 39.429 ;
        RECT  0 38.871 0.018 38.889 ;
        RECT  0 38.331 0.018 38.349 ;
        RECT  0 37.791 0.018 37.809 ;
        RECT  0 37.251 0.018 37.269 ;
        RECT  0 36.711 0.018 36.729 ;
        RECT  0 36.171 0.018 36.189 ;
        RECT  0 35.631 0.018 35.649 ;
        RECT  0 35.091 0.018 35.109 ;
        RECT  0 34.551 0.018 34.569 ;
        RECT  0 34.011 0.018 34.029 ;
        RECT  0 33.471 0.018 33.489 ;
        RECT  0 32.931 0.018 32.949 ;
        RECT  0 32.391 0.018 32.409 ;
        RECT  0 31.851 0.018 31.869 ;
        RECT  0 31.311 0.018 31.329 ;
        RECT  0 30.771 0.018 30.789 ;
        RECT  0 30.231 0.018 30.249 ;
        RECT  0 29.691 0.018 29.709 ;
        RECT  0 29.151 0.018 29.169 ;
        RECT  0 28.611 0.018 28.629 ;
        RECT  0 28.071 0.018 28.089 ;
        RECT  0 27.531 0.018 27.549 ;
        RECT  0 26.991 0.018 27.009 ;
        RECT  0 26.451 0.018 26.469 ;
        RECT  0 25.911 0.018 25.929 ;
        RECT  0 25.371 0.018 25.389 ;
        RECT  0 24.831 0.018 24.849 ;
        RECT  0 24.291 0.018 24.309 ;
        RECT  0 23.751 0.018 23.769 ;
        RECT  0 23.211 0.018 23.229 ;
        RECT  0 22.671 0.018 22.689 ;
        RECT  0 22.131 0.018 22.149 ;
        RECT  0 21.591 0.018 21.609 ;
        RECT  0 21.051 0.018 21.069 ;
        RECT  0 20.511 0.018 20.529 ;
        RECT  0 19.971 0.018 19.989 ;
        RECT  0 19.431 0.018 19.449 ;
        RECT  0 18.891 0.018 18.909 ;
        RECT  0 18.351 0.018 18.369 ;
        RECT  0 17.811 0.018 17.829 ;
        RECT  0 17.271 0.018 17.289 ;
        RECT  0 16.731 0.018 16.749 ;
        RECT  0 16.191 0.018 16.209 ;
        RECT  0 15.651 0.018 15.669 ;
        RECT  0 15.111 0.018 15.129 ;
        RECT  0 14.571 0.018 14.589 ;
        RECT  0 14.031 0.018 14.049 ;
        RECT  0 13.491 0.018 13.509 ;
        RECT  0 12.951 0.018 12.969 ;
        RECT  0 12.411 0.018 12.429 ;
        RECT  0 11.871 0.018 11.889 ;
        RECT  0 11.331 0.018 11.349 ;
        RECT  0 10.791 0.018 10.809 ;
        RECT  0 10.251 0.018 10.269 ;
        RECT  0 9.711 0.018 9.729 ;
        RECT  0 9.171 0.018 9.189 ;
        RECT  0 8.631 0.018 8.649 ;
        RECT  0 8.091 0.018 8.109 ;
        RECT  0 7.551 0.018 7.569 ;
        RECT  0 7.011 0.018 7.029 ;
        RECT  0 6.471 0.018 6.489 ;
        RECT  0 5.931 0.018 5.949 ;
        RECT  0 5.391 0.018 5.409 ;
        RECT  0 4.851 0.018 4.869 ;
        RECT  0 4.311 0.018 4.329 ;
        RECT  0 3.771 0.018 3.789 ;
        RECT  0 3.231 0.018 3.249 ;
        RECT  0 2.691 0.018 2.709 ;
        RECT  0 2.151 0.018 2.169 ;
        RECT  0 1.611 0.018 1.629 ;
        RECT  0 1.071 0.018 1.089 ;
        RECT  0 0.531 0.018 0.549 ;
      LAYER M1 ;
        RECT  0 141.471 0.018 141.489 ;
        RECT  0 140.931 0.018 140.949 ;
        RECT  0 140.391 0.018 140.409 ;
        RECT  0 139.851 0.018 139.869 ;
        RECT  0 139.311 0.018 139.329 ;
        RECT  0 138.771 0.018 138.789 ;
        RECT  0 138.231 0.018 138.249 ;
        RECT  0 137.691 0.018 137.709 ;
        RECT  0 137.151 0.018 137.169 ;
        RECT  0 136.611 0.018 136.629 ;
        RECT  0 136.071 0.018 136.089 ;
        RECT  0 135.531 0.018 135.549 ;
        RECT  0 134.991 0.018 135.009 ;
        RECT  0 134.451 0.018 134.469 ;
        RECT  0 133.911 0.018 133.929 ;
        RECT  0 133.371 0.018 133.389 ;
        RECT  0 132.831 0.018 132.849 ;
        RECT  0 132.291 0.018 132.309 ;
        RECT  0 131.751 0.018 131.769 ;
        RECT  0 131.211 0.018 131.229 ;
        RECT  0 130.671 0.018 130.689 ;
        RECT  0 130.131 0.018 130.149 ;
        RECT  0 129.591 0.018 129.609 ;
        RECT  0 129.051 0.018 129.069 ;
        RECT  0 128.511 0.018 128.529 ;
        RECT  0 127.971 0.018 127.989 ;
        RECT  0 127.431 0.018 127.449 ;
        RECT  0 126.891 0.018 126.909 ;
        RECT  0 126.351 0.018 126.369 ;
        RECT  0 125.811 0.018 125.829 ;
        RECT  0 125.271 0.018 125.289 ;
        RECT  0 124.731 0.018 124.749 ;
        RECT  0 124.191 0.018 124.209 ;
        RECT  0 123.651 0.018 123.669 ;
        RECT  0 123.111 0.018 123.129 ;
        RECT  0 122.571 0.018 122.589 ;
        RECT  0 122.031 0.018 122.049 ;
        RECT  0 121.491 0.018 121.509 ;
        RECT  0 120.951 0.018 120.969 ;
        RECT  0 120.411 0.018 120.429 ;
        RECT  0 119.871 0.018 119.889 ;
        RECT  0 119.331 0.018 119.349 ;
        RECT  0 118.791 0.018 118.809 ;
        RECT  0 118.251 0.018 118.269 ;
        RECT  0 117.711 0.018 117.729 ;
        RECT  0 117.171 0.018 117.189 ;
        RECT  0 116.631 0.018 116.649 ;
        RECT  0 116.091 0.018 116.109 ;
        RECT  0 115.551 0.018 115.569 ;
        RECT  0 115.011 0.018 115.029 ;
        RECT  0 114.471 0.018 114.489 ;
        RECT  0 113.931 0.018 113.949 ;
        RECT  0 113.391 0.018 113.409 ;
        RECT  0 112.851 0.018 112.869 ;
        RECT  0 112.311 0.018 112.329 ;
        RECT  0 111.771 0.018 111.789 ;
        RECT  0 111.231 0.018 111.249 ;
        RECT  0 110.691 0.018 110.709 ;
        RECT  0 110.151 0.018 110.169 ;
        RECT  0 109.611 0.018 109.629 ;
        RECT  0 109.071 0.018 109.089 ;
        RECT  0 108.531 0.018 108.549 ;
        RECT  0 107.991 0.018 108.009 ;
        RECT  0 107.451 0.018 107.469 ;
        RECT  0 106.911 0.018 106.929 ;
        RECT  0 106.371 0.018 106.389 ;
        RECT  0 105.831 0.018 105.849 ;
        RECT  0 105.291 0.018 105.309 ;
        RECT  0 104.751 0.018 104.769 ;
        RECT  0 104.211 0.018 104.229 ;
        RECT  0 103.671 0.018 103.689 ;
        RECT  0 103.131 0.018 103.149 ;
        RECT  0 102.591 0.018 102.609 ;
        RECT  0 102.051 0.018 102.069 ;
        RECT  0 101.511 0.018 101.529 ;
        RECT  0 100.971 0.018 100.989 ;
        RECT  0 100.431 0.018 100.449 ;
        RECT  0 99.891 0.018 99.909 ;
        RECT  0 99.351 0.018 99.369 ;
        RECT  0 98.811 0.018 98.829 ;
        RECT  0 98.271 0.018 98.289 ;
        RECT  0 97.731 0.018 97.749 ;
        RECT  0 97.191 0.018 97.209 ;
        RECT  0 96.651 0.018 96.669 ;
        RECT  0 96.111 0.018 96.129 ;
        RECT  0 95.571 0.018 95.589 ;
        RECT  0 95.031 0.018 95.049 ;
        RECT  0 94.491 0.018 94.509 ;
        RECT  0 93.951 0.018 93.969 ;
        RECT  0 93.411 0.018 93.429 ;
        RECT  0 92.871 0.018 92.889 ;
        RECT  0 92.331 0.018 92.349 ;
        RECT  0 91.791 0.018 91.809 ;
        RECT  0 91.251 0.018 91.269 ;
        RECT  0 90.711 0.018 90.729 ;
        RECT  0 90.171 0.018 90.189 ;
        RECT  0 89.631 0.018 89.649 ;
        RECT  0 89.091 0.018 89.109 ;
        RECT  0 88.551 0.018 88.569 ;
        RECT  0 88.011 0.018 88.029 ;
        RECT  0 87.471 0.018 87.489 ;
        RECT  0 86.931 0.018 86.949 ;
        RECT  0 86.391 0.018 86.409 ;
        RECT  0 85.851 0.018 85.869 ;
        RECT  0 85.311 0.018 85.329 ;
        RECT  0 84.771 0.018 84.789 ;
        RECT  0 84.231 0.018 84.249 ;
        RECT  0 83.691 0.018 83.709 ;
        RECT  0 83.151 0.018 83.169 ;
        RECT  0 82.611 0.018 82.629 ;
        RECT  0 82.071 0.018 82.089 ;
        RECT  0 81.531 0.018 81.549 ;
        RECT  0 80.991 0.018 81.009 ;
        RECT  0 80.451 0.018 80.469 ;
        RECT  0 79.911 0.018 79.929 ;
        RECT  0 79.371 0.018 79.389 ;
        RECT  0 78.831 0.018 78.849 ;
        RECT  0 78.291 0.018 78.309 ;
        RECT  0 77.751 0.018 77.769 ;
        RECT  0 77.211 0.018 77.229 ;
        RECT  0 76.671 0.018 76.689 ;
        RECT  0 76.131 0.018 76.149 ;
        RECT  0 75.591 0.018 75.609 ;
        RECT  0 75.051 0.018 75.069 ;
        RECT  0 74.511 0.018 74.529 ;
        RECT  0 73.971 0.018 73.989 ;
        RECT  0 73.431 0.018 73.449 ;
        RECT  0 72.891 0.018 72.909 ;
        RECT  0 72.351 0.018 72.369 ;
        RECT  0 71.811 0.018 71.829 ;
        RECT  0 71.271 0.018 71.289 ;
        RECT  0 70.731 0.018 70.749 ;
        RECT  0 70.191 0.018 70.209 ;
        RECT  0 69.651 0.018 69.669 ;
        RECT  0 69.111 0.018 69.129 ;
        RECT  0 68.571 0.018 68.589 ;
        RECT  0 68.031 0.018 68.049 ;
        RECT  0 67.491 0.018 67.509 ;
        RECT  0 66.951 0.018 66.969 ;
        RECT  0 66.411 0.018 66.429 ;
        RECT  0 65.871 0.018 65.889 ;
        RECT  0 65.331 0.018 65.349 ;
        RECT  0 64.791 0.018 64.809 ;
        RECT  0 64.251 0.018 64.269 ;
        RECT  0 63.711 0.018 63.729 ;
        RECT  0 63.171 0.018 63.189 ;
        RECT  0 62.631 0.018 62.649 ;
        RECT  0 62.091 0.018 62.109 ;
        RECT  0 61.551 0.018 61.569 ;
        RECT  0 61.011 0.018 61.029 ;
        RECT  0 60.471 0.018 60.489 ;
        RECT  0 59.931 0.018 59.949 ;
        RECT  0 59.391 0.018 59.409 ;
        RECT  0 58.851 0.018 58.869 ;
        RECT  0 58.311 0.018 58.329 ;
        RECT  0 57.771 0.018 57.789 ;
        RECT  0 57.231 0.018 57.249 ;
        RECT  0 56.691 0.018 56.709 ;
        RECT  0 56.151 0.018 56.169 ;
        RECT  0 55.611 0.018 55.629 ;
        RECT  0 55.071 0.018 55.089 ;
        RECT  0 54.531 0.018 54.549 ;
        RECT  0 53.991 0.018 54.009 ;
        RECT  0 53.451 0.018 53.469 ;
        RECT  0 52.911 0.018 52.929 ;
        RECT  0 52.371 0.018 52.389 ;
        RECT  0 51.831 0.018 51.849 ;
        RECT  0 51.291 0.018 51.309 ;
        RECT  0 50.751 0.018 50.769 ;
        RECT  0 50.211 0.018 50.229 ;
        RECT  0 49.671 0.018 49.689 ;
        RECT  0 49.131 0.018 49.149 ;
        RECT  0 48.591 0.018 48.609 ;
        RECT  0 48.051 0.018 48.069 ;
        RECT  0 47.511 0.018 47.529 ;
        RECT  0 46.971 0.018 46.989 ;
        RECT  0 46.431 0.018 46.449 ;
        RECT  0 45.891 0.018 45.909 ;
        RECT  0 45.351 0.018 45.369 ;
        RECT  0 44.811 0.018 44.829 ;
        RECT  0 44.271 0.018 44.289 ;
        RECT  0 43.731 0.018 43.749 ;
        RECT  0 43.191 0.018 43.209 ;
        RECT  0 42.651 0.018 42.669 ;
        RECT  0 42.111 0.018 42.129 ;
        RECT  0 41.571 0.018 41.589 ;
        RECT  0 41.031 0.018 41.049 ;
        RECT  0 40.491 0.018 40.509 ;
        RECT  0 39.951 0.018 39.969 ;
        RECT  0 39.411 0.018 39.429 ;
        RECT  0 38.871 0.018 38.889 ;
        RECT  0 38.331 0.018 38.349 ;
        RECT  0 37.791 0.018 37.809 ;
        RECT  0 37.251 0.018 37.269 ;
        RECT  0 36.711 0.018 36.729 ;
        RECT  0 36.171 0.018 36.189 ;
        RECT  0 35.631 0.018 35.649 ;
        RECT  0 35.091 0.018 35.109 ;
        RECT  0 34.551 0.018 34.569 ;
        RECT  0 34.011 0.018 34.029 ;
        RECT  0 33.471 0.018 33.489 ;
        RECT  0 32.931 0.018 32.949 ;
        RECT  0 32.391 0.018 32.409 ;
        RECT  0 31.851 0.018 31.869 ;
        RECT  0 31.311 0.018 31.329 ;
        RECT  0 30.771 0.018 30.789 ;
        RECT  0 30.231 0.018 30.249 ;
        RECT  0 29.691 0.018 29.709 ;
        RECT  0 29.151 0.018 29.169 ;
        RECT  0 28.611 0.018 28.629 ;
        RECT  0 28.071 0.018 28.089 ;
        RECT  0 27.531 0.018 27.549 ;
        RECT  0 26.991 0.018 27.009 ;
        RECT  0 26.451 0.018 26.469 ;
        RECT  0 25.911 0.018 25.929 ;
        RECT  0 25.371 0.018 25.389 ;
        RECT  0 24.831 0.018 24.849 ;
        RECT  0 24.291 0.018 24.309 ;
        RECT  0 23.751 0.018 23.769 ;
        RECT  0 23.211 0.018 23.229 ;
        RECT  0 22.671 0.018 22.689 ;
        RECT  0 22.131 0.018 22.149 ;
        RECT  0 21.591 0.018 21.609 ;
        RECT  0 21.051 0.018 21.069 ;
        RECT  0 20.511 0.018 20.529 ;
        RECT  0 19.971 0.018 19.989 ;
        RECT  0 19.431 0.018 19.449 ;
        RECT  0 18.891 0.018 18.909 ;
        RECT  0 18.351 0.018 18.369 ;
        RECT  0 17.811 0.018 17.829 ;
        RECT  0 17.271 0.018 17.289 ;
        RECT  0 16.731 0.018 16.749 ;
        RECT  0 16.191 0.018 16.209 ;
        RECT  0 15.651 0.018 15.669 ;
        RECT  0 15.111 0.018 15.129 ;
        RECT  0 14.571 0.018 14.589 ;
        RECT  0 14.031 0.018 14.049 ;
        RECT  0 13.491 0.018 13.509 ;
        RECT  0 12.951 0.018 12.969 ;
        RECT  0 12.411 0.018 12.429 ;
        RECT  0 11.871 0.018 11.889 ;
        RECT  0 11.331 0.018 11.349 ;
        RECT  0 10.791 0.018 10.809 ;
        RECT  0 10.251 0.018 10.269 ;
        RECT  0 9.711 0.018 9.729 ;
        RECT  0 9.171 0.018 9.189 ;
        RECT  0 8.631 0.018 8.649 ;
        RECT  0 8.091 0.018 8.109 ;
        RECT  0 7.551 0.018 7.569 ;
        RECT  0 7.011 0.018 7.029 ;
        RECT  0 6.471 0.018 6.489 ;
        RECT  0 5.931 0.018 5.949 ;
        RECT  0 5.391 0.018 5.409 ;
        RECT  0 4.851 0.018 4.869 ;
        RECT  0 4.311 0.018 4.329 ;
        RECT  0 3.771 0.018 3.789 ;
        RECT  0 3.231 0.018 3.249 ;
        RECT  0 2.691 0.018 2.709 ;
        RECT  0 2.151 0.018 2.169 ;
        RECT  0 1.611 0.018 1.629 ;
        RECT  0 1.071 0.018 1.089 ;
        RECT  0 0.531 0.018 0.549 ;
    END
  END VSS
  OBS
    LAYER RVTN ;
     RECT  0 0.54 14.634 0.675 ;
     RECT  0 0.945 14.634 1.215 ;
     RECT  0 1.485 14.634 1.755 ;
     RECT  0 2.025 14.634 2.295 ;
     RECT  0 2.565 14.634 2.835 ;
     RECT  0 3.105 14.634 3.375 ;
     RECT  0 3.645 14.634 3.915 ;
     RECT  0 4.185 14.634 4.455 ;
     RECT  0 4.725 14.634 4.995 ;
     RECT  0 5.265 14.634 5.535 ;
     RECT  0 5.805 14.634 6.075 ;
     RECT  0 6.345 14.634 6.615 ;
     RECT  0 6.885 14.634 7.155 ;
     RECT  0 7.425 14.634 7.695 ;
     RECT  0 7.965 14.634 8.235 ;
     RECT  0 8.505 14.634 8.775 ;
     RECT  0 9.045 14.634 9.315 ;
     RECT  0 9.585 14.634 9.855 ;
     RECT  0 10.125 14.634 10.395 ;
     RECT  0 10.665 14.634 10.935 ;
     RECT  0 11.205 14.634 11.475 ;
     RECT  0 11.745 14.634 12.015 ;
     RECT  0 12.285 14.634 12.555 ;
     RECT  0 12.825 14.634 13.095 ;
     RECT  0 13.365 14.634 13.635 ;
     RECT  0 13.905 14.634 14.175 ;
     RECT  0 14.445 14.634 14.715 ;
     RECT  0 14.985 14.634 15.255 ;
     RECT  0 15.525 14.634 15.795 ;
     RECT  0 16.065 14.634 16.335 ;
     RECT  0 16.605 14.634 16.875 ;
     RECT  0 17.145 14.634 17.415 ;
     RECT  0 17.685 14.634 17.955 ;
     RECT  0 18.225 14.634 18.495 ;
     RECT  0 18.765 14.634 19.035 ;
     RECT  0 19.305 14.634 19.575 ;
     RECT  0 19.845 14.634 20.115 ;
     RECT  0 20.385 14.634 20.655 ;
     RECT  0 20.925 14.634 21.195 ;
     RECT  0 21.465 14.634 21.735 ;
     RECT  0 22.005 14.634 22.275 ;
     RECT  0 22.545 14.634 22.815 ;
     RECT  0 23.085 14.634 23.355 ;
     RECT  0 23.625 14.634 23.895 ;
     RECT  0 24.165 14.634 24.435 ;
     RECT  0 24.705 14.634 24.975 ;
     RECT  0 25.245 14.634 25.515 ;
     RECT  0 25.785 14.634 26.055 ;
     RECT  0 26.325 14.634 26.595 ;
     RECT  0 26.865 14.634 27.135 ;
     RECT  0 27.405 14.634 27.675 ;
     RECT  0 27.945 14.634 28.215 ;
     RECT  0 28.485 14.634 28.755 ;
     RECT  0 29.025 14.634 29.295 ;
     RECT  0 29.565 14.634 29.835 ;
     RECT  0 30.105 14.634 30.375 ;
     RECT  0 30.645 14.634 30.915 ;
     RECT  0 31.185 14.634 31.455 ;
     RECT  0 31.725 14.634 31.995 ;
     RECT  0 32.265 14.634 32.535 ;
     RECT  0 32.805 14.634 33.075 ;
     RECT  0 33.345 14.634 33.615 ;
     RECT  0 33.885 14.634 34.155 ;
     RECT  0 34.425 14.634 34.695 ;
     RECT  0 34.965 14.634 35.235 ;
     RECT  0 35.505 14.634 35.775 ;
     RECT  0 36.045 14.634 36.315 ;
     RECT  0 36.585 14.634 36.855 ;
     RECT  0 37.125 14.634 37.395 ;
     RECT  0 37.665 14.634 37.935 ;
     RECT  0 38.205 14.634 38.475 ;
     RECT  0 38.745 14.634 39.015 ;
     RECT  0 39.285 14.634 39.555 ;
     RECT  0 39.825 14.634 40.095 ;
     RECT  0 40.365 14.634 40.635 ;
     RECT  0 40.905 14.634 41.175 ;
     RECT  0 41.445 14.634 41.715 ;
     RECT  0 41.985 14.634 42.255 ;
     RECT  0 42.525 14.634 42.795 ;
     RECT  0 43.065 14.634 43.335 ;
     RECT  0 43.605 14.634 43.875 ;
     RECT  0 44.145 14.634 44.415 ;
     RECT  0 44.685 14.634 44.955 ;
     RECT  0 45.225 14.634 45.495 ;
     RECT  0 45.765 14.634 46.035 ;
     RECT  0 46.305 14.634 46.575 ;
     RECT  0 46.845 14.634 47.115 ;
     RECT  0 47.385 14.634 47.655 ;
     RECT  0 47.925 14.634 48.195 ;
     RECT  0 48.465 14.634 48.735 ;
     RECT  0 49.005 14.634 49.275 ;
     RECT  0 49.545 14.634 49.815 ;
     RECT  0 50.085 14.634 50.355 ;
     RECT  0 50.625 14.634 50.895 ;
     RECT  0 51.165 14.634 51.435 ;
     RECT  0 51.705 14.634 51.975 ;
     RECT  0 52.245 14.634 52.515 ;
     RECT  0 52.785 14.634 53.055 ;
     RECT  0 53.325 14.634 53.595 ;
     RECT  0 53.865 14.634 54.135 ;
     RECT  0 54.405 14.634 54.675 ;
     RECT  0 54.945 14.634 55.215 ;
     RECT  0 55.485 14.634 55.755 ;
     RECT  0 56.025 14.634 56.295 ;
     RECT  0 56.565 14.634 56.835 ;
     RECT  0 57.105 14.634 57.375 ;
     RECT  0 57.645 14.634 57.915 ;
     RECT  0 58.185 14.634 58.455 ;
     RECT  0 58.725 14.634 58.995 ;
     RECT  0 59.265 14.634 59.535 ;
     RECT  0 59.805 14.634 60.075 ;
     RECT  0 60.345 14.634 60.615 ;
     RECT  0 60.885 14.634 61.155 ;
     RECT  0 61.425 14.634 61.695 ;
     RECT  0 61.965 14.634 62.235 ;
     RECT  0 62.505 14.634 62.775 ;
     RECT  0 63.045 14.634 63.315 ;
     RECT  0 63.585 14.634 63.855 ;
     RECT  0 64.125 14.634 64.395 ;
     RECT  0 64.665 14.634 64.935 ;
     RECT  0 65.205 14.634 65.475 ;
     RECT  0 65.745 14.634 66.015 ;
     RECT  0 66.285 14.634 66.555 ;
     RECT  0 66.825 14.634 67.095 ;
     RECT  0 67.365 14.634 67.635 ;
     RECT  0 67.905 14.634 68.175 ;
     RECT  0 68.445 14.634 68.715 ;
     RECT  0 68.985 14.634 69.255 ;
     RECT  0 69.525 14.634 69.795 ;
     RECT  0 70.065 14.634 70.335 ;
     RECT  0 70.605 14.634 70.875 ;
     RECT  0 71.145 14.634 71.415 ;
     RECT  0 71.685 14.634 71.955 ;
     RECT  0 72.225 14.634 72.495 ;
     RECT  0 72.765 14.634 73.035 ;
     RECT  0 73.305 14.634 73.575 ;
     RECT  0 73.845 14.634 74.115 ;
     RECT  0 74.385 14.634 74.655 ;
     RECT  0 74.925 14.634 75.195 ;
     RECT  0 75.465 14.634 75.735 ;
     RECT  0 76.005 14.634 76.275 ;
     RECT  0 76.545 14.634 76.815 ;
     RECT  0 77.085 14.634 77.355 ;
     RECT  0 77.625 14.634 77.895 ;
     RECT  0 78.165 14.634 78.435 ;
     RECT  0 78.705 14.634 78.975 ;
     RECT  0 79.245 14.634 79.515 ;
     RECT  0 79.785 14.634 80.055 ;
     RECT  0 80.325 14.634 80.595 ;
     RECT  0 80.865 14.634 81.135 ;
     RECT  0 81.405 14.634 81.675 ;
     RECT  0 81.945 14.634 82.215 ;
     RECT  0 82.485 14.634 82.755 ;
     RECT  0 83.025 14.634 83.295 ;
     RECT  0 83.565 14.634 83.835 ;
     RECT  0 84.105 14.634 84.375 ;
     RECT  0 84.645 14.634 84.915 ;
     RECT  0 85.185 14.634 85.455 ;
     RECT  0 85.725 14.634 85.995 ;
     RECT  0 86.265 14.634 86.535 ;
     RECT  0 86.805 14.634 87.075 ;
     RECT  0 87.345 14.634 87.615 ;
     RECT  0 87.885 14.634 88.155 ;
     RECT  0 88.425 14.634 88.695 ;
     RECT  0 88.965 14.634 89.235 ;
     RECT  0 89.505 14.634 89.775 ;
     RECT  0 90.045 14.634 90.315 ;
     RECT  0 90.585 14.634 90.855 ;
     RECT  0 91.125 14.634 91.395 ;
     RECT  0 91.665 14.634 91.935 ;
     RECT  0 92.205 14.634 92.475 ;
     RECT  0 92.745 14.634 93.015 ;
     RECT  0 93.285 14.634 93.555 ;
     RECT  0 93.825 14.634 94.095 ;
     RECT  0 94.365 14.634 94.635 ;
     RECT  0 94.905 14.634 95.175 ;
     RECT  0 95.445 14.634 95.715 ;
     RECT  0 95.985 14.634 96.255 ;
     RECT  0 96.525 14.634 96.795 ;
     RECT  0 97.065 14.634 97.335 ;
     RECT  0 97.605 14.634 97.875 ;
     RECT  0 98.145 14.634 98.415 ;
     RECT  0 98.685 14.634 98.955 ;
     RECT  0 99.225 14.634 99.495 ;
     RECT  0 99.765 14.634 100.035 ;
     RECT  0 100.305 14.634 100.575 ;
     RECT  0 100.845 14.634 101.115 ;
     RECT  0 101.385 14.634 101.655 ;
     RECT  0 101.925 14.634 102.195 ;
     RECT  0 102.465 14.634 102.735 ;
     RECT  0 103.005 14.634 103.275 ;
     RECT  0 103.545 14.634 103.815 ;
     RECT  0 104.085 14.634 104.355 ;
     RECT  0 104.625 14.634 104.895 ;
     RECT  0 105.165 14.634 105.435 ;
     RECT  0 105.705 14.634 105.975 ;
     RECT  0 106.245 14.634 106.515 ;
     RECT  0 106.785 14.634 107.055 ;
     RECT  0 107.325 14.634 107.595 ;
     RECT  0 107.865 14.634 108.135 ;
     RECT  0 108.405 14.634 108.675 ;
     RECT  0 108.945 14.634 109.215 ;
     RECT  0 109.485 14.634 109.755 ;
     RECT  0 110.025 14.634 110.295 ;
     RECT  0 110.565 14.634 110.835 ;
     RECT  0 111.105 14.634 111.375 ;
     RECT  0 111.645 14.634 111.915 ;
     RECT  0 112.185 14.634 112.455 ;
     RECT  0 112.725 14.634 112.995 ;
     RECT  0 113.265 14.634 113.535 ;
     RECT  0 113.805 14.634 114.075 ;
     RECT  0 114.345 14.634 114.615 ;
     RECT  0 114.885 14.634 115.155 ;
     RECT  0 115.425 14.634 115.695 ;
     RECT  0 115.965 14.634 116.235 ;
     RECT  0 116.505 14.634 116.775 ;
     RECT  0 117.045 14.634 117.315 ;
     RECT  0 117.585 14.634 117.855 ;
     RECT  0 118.125 14.634 118.395 ;
     RECT  0 118.665 14.634 118.935 ;
     RECT  0 119.205 14.634 119.475 ;
     RECT  0 119.745 14.634 120.015 ;
     RECT  0 120.285 14.634 120.555 ;
     RECT  0 120.825 14.634 121.095 ;
     RECT  0 121.365 14.634 121.635 ;
     RECT  0 121.905 14.634 122.175 ;
     RECT  0 122.445 14.634 122.715 ;
     RECT  0 122.985 14.634 123.255 ;
     RECT  0 123.525 14.634 123.795 ;
     RECT  0 124.065 14.634 124.335 ;
     RECT  0 124.605 14.634 124.875 ;
     RECT  0 125.145 14.634 125.415 ;
     RECT  0 125.685 14.634 125.955 ;
     RECT  0 126.225 14.634 126.495 ;
     RECT  0 126.765 14.634 127.035 ;
     RECT  0 127.305 14.634 127.575 ;
     RECT  0 127.845 14.634 128.115 ;
     RECT  0 128.385 14.634 128.655 ;
     RECT  0 128.925 14.634 129.195 ;
     RECT  0 129.465 14.634 129.735 ;
     RECT  0 130.005 14.634 130.275 ;
     RECT  0 130.545 14.634 130.815 ;
     RECT  0 131.085 14.634 131.355 ;
     RECT  0 131.625 14.634 131.895 ;
     RECT  0 132.165 14.634 132.435 ;
     RECT  0 132.705 14.634 132.975 ;
     RECT  0 133.245 14.634 133.515 ;
     RECT  0 133.785 14.634 134.055 ;
     RECT  0 134.325 14.634 134.595 ;
     RECT  0 134.865 14.634 135.135 ;
     RECT  0 135.405 14.634 135.675 ;
     RECT  0 135.945 14.634 136.215 ;
     RECT  0 136.485 14.634 136.755 ;
     RECT  0 137.025 14.634 137.295 ;
     RECT  0 137.565 14.634 137.835 ;
     RECT  0 138.105 14.634 138.375 ;
     RECT  0 138.645 14.634 138.915 ;
     RECT  0 139.185 14.634 139.455 ;
     RECT  0 139.725 14.634 139.995 ;
     RECT  0 140.265 14.634 140.535 ;
     RECT  0 140.805 14.634 141.075 ;
     RECT  0 141.345 14.634 141.615 ;
    LAYER RVTP ;
     RECT  0 0.675 14.634 0.945 ;
     RECT  0 1.215 14.634 1.485 ;
     RECT  0 1.755 14.634 2.025 ;
     RECT  0 2.295 14.634 2.565 ;
     RECT  0 2.835 14.634 3.105 ;
     RECT  0 3.375 14.634 3.645 ;
     RECT  0 3.915 14.634 4.185 ;
     RECT  0 4.455 14.634 4.725 ;
     RECT  0 4.995 14.634 5.265 ;
     RECT  0 5.535 14.634 5.805 ;
     RECT  0 6.075 14.634 6.345 ;
     RECT  0 6.615 14.634 6.885 ;
     RECT  0 7.155 14.634 7.425 ;
     RECT  0 7.695 14.634 7.965 ;
     RECT  0 8.235 14.634 8.505 ;
     RECT  0 8.775 14.634 9.045 ;
     RECT  0 9.315 14.634 9.585 ;
     RECT  0 9.855 14.634 10.125 ;
     RECT  0 10.395 14.634 10.665 ;
     RECT  0 10.935 14.634 11.205 ;
     RECT  0 11.475 14.634 11.745 ;
     RECT  0 12.015 14.634 12.285 ;
     RECT  0 12.555 14.634 12.825 ;
     RECT  0 13.095 14.634 13.365 ;
     RECT  0 13.635 14.634 13.905 ;
     RECT  0 14.175 14.634 14.445 ;
     RECT  0 14.715 14.634 14.985 ;
     RECT  0 15.255 14.634 15.525 ;
     RECT  0 15.795 14.634 16.065 ;
     RECT  0 16.335 14.634 16.605 ;
     RECT  0 16.875 14.634 17.145 ;
     RECT  0 17.415 14.634 17.685 ;
     RECT  0 17.955 14.634 18.225 ;
     RECT  0 18.495 14.634 18.765 ;
     RECT  0 19.035 14.634 19.305 ;
     RECT  0 19.575 14.634 19.845 ;
     RECT  0 20.115 14.634 20.385 ;
     RECT  0 20.655 14.634 20.925 ;
     RECT  0 21.195 14.634 21.465 ;
     RECT  0 21.735 14.634 22.005 ;
     RECT  0 22.275 14.634 22.545 ;
     RECT  0 22.815 14.634 23.085 ;
     RECT  0 23.355 14.634 23.625 ;
     RECT  0 23.895 14.634 24.165 ;
     RECT  0 24.435 14.634 24.705 ;
     RECT  0 24.975 14.634 25.245 ;
     RECT  0 25.515 14.634 25.785 ;
     RECT  0 26.055 14.634 26.325 ;
     RECT  0 26.595 14.634 26.865 ;
     RECT  0 27.135 14.634 27.405 ;
     RECT  0 27.675 14.634 27.945 ;
     RECT  0 28.215 14.634 28.485 ;
     RECT  0 28.755 14.634 29.025 ;
     RECT  0 29.295 14.634 29.565 ;
     RECT  0 29.835 14.634 30.105 ;
     RECT  0 30.375 14.634 30.645 ;
     RECT  0 30.915 14.634 31.185 ;
     RECT  0 31.455 14.634 31.725 ;
     RECT  0 31.995 14.634 32.265 ;
     RECT  0 32.535 14.634 32.805 ;
     RECT  0 33.075 14.634 33.345 ;
     RECT  0 33.615 14.634 33.885 ;
     RECT  0 34.155 14.634 34.425 ;
     RECT  0 34.695 14.634 34.965 ;
     RECT  0 35.235 14.634 35.505 ;
     RECT  0 35.775 14.634 36.045 ;
     RECT  0 36.315 14.634 36.585 ;
     RECT  0 36.855 14.634 37.125 ;
     RECT  0 37.395 14.634 37.665 ;
     RECT  0 37.935 14.634 38.205 ;
     RECT  0 38.475 14.634 38.745 ;
     RECT  0 39.015 14.634 39.285 ;
     RECT  0 39.555 14.634 39.825 ;
     RECT  0 40.095 14.634 40.365 ;
     RECT  0 40.635 14.634 40.905 ;
     RECT  0 41.175 14.634 41.445 ;
     RECT  0 41.715 14.634 41.985 ;
     RECT  0 42.255 14.634 42.525 ;
     RECT  0 42.795 14.634 43.065 ;
     RECT  0 43.335 14.634 43.605 ;
     RECT  0 43.875 14.634 44.145 ;
     RECT  0 44.415 14.634 44.685 ;
     RECT  0 44.955 14.634 45.225 ;
     RECT  0 45.495 14.634 45.765 ;
     RECT  0 46.035 14.634 46.305 ;
     RECT  0 46.575 14.634 46.845 ;
     RECT  0 47.115 14.634 47.385 ;
     RECT  0 47.655 14.634 47.925 ;
     RECT  0 48.195 14.634 48.465 ;
     RECT  0 48.735 14.634 49.005 ;
     RECT  0 49.275 14.634 49.545 ;
     RECT  0 49.815 14.634 50.085 ;
     RECT  0 50.355 14.634 50.625 ;
     RECT  0 50.895 14.634 51.165 ;
     RECT  0 51.435 14.634 51.705 ;
     RECT  0 51.975 14.634 52.245 ;
     RECT  0 52.515 14.634 52.785 ;
     RECT  0 53.055 14.634 53.325 ;
     RECT  0 53.595 14.634 53.865 ;
     RECT  0 54.135 14.634 54.405 ;
     RECT  0 54.675 14.634 54.945 ;
     RECT  0 55.215 14.634 55.485 ;
     RECT  0 55.755 14.634 56.025 ;
     RECT  0 56.295 14.634 56.565 ;
     RECT  0 56.835 14.634 57.105 ;
     RECT  0 57.375 14.634 57.645 ;
     RECT  0 57.915 14.634 58.185 ;
     RECT  0 58.455 14.634 58.725 ;
     RECT  0 58.995 14.634 59.265 ;
     RECT  0 59.535 14.634 59.805 ;
     RECT  0 60.075 14.634 60.345 ;
     RECT  0 60.615 14.634 60.885 ;
     RECT  0 61.155 14.634 61.425 ;
     RECT  0 61.695 14.634 61.965 ;
     RECT  0 62.235 14.634 62.505 ;
     RECT  0 62.775 14.634 63.045 ;
     RECT  0 63.315 14.634 63.585 ;
     RECT  0 63.855 14.634 64.125 ;
     RECT  0 64.395 14.634 64.665 ;
     RECT  0 64.935 14.634 65.205 ;
     RECT  0 65.475 14.634 65.745 ;
     RECT  0 66.015 14.634 66.285 ;
     RECT  0 66.555 14.634 66.825 ;
     RECT  0 67.095 14.634 67.365 ;
     RECT  0 67.635 14.634 67.905 ;
     RECT  0 68.175 14.634 68.445 ;
     RECT  0 68.715 14.634 68.985 ;
     RECT  0 69.255 14.634 69.525 ;
     RECT  0 69.795 14.634 70.065 ;
     RECT  0 70.335 14.634 70.605 ;
     RECT  0 70.875 14.634 71.145 ;
     RECT  0 71.415 14.634 71.685 ;
     RECT  0 71.955 14.634 72.225 ;
     RECT  0 72.495 14.634 72.765 ;
     RECT  0 73.035 14.634 73.305 ;
     RECT  0 73.575 14.634 73.845 ;
     RECT  0 74.115 14.634 74.385 ;
     RECT  0 74.655 14.634 74.925 ;
     RECT  0 75.195 14.634 75.465 ;
     RECT  0 75.735 14.634 76.005 ;
     RECT  0 76.275 14.634 76.545 ;
     RECT  0 76.815 14.634 77.085 ;
     RECT  0 77.355 14.634 77.625 ;
     RECT  0 77.895 14.634 78.165 ;
     RECT  0 78.435 14.634 78.705 ;
     RECT  0 78.975 14.634 79.245 ;
     RECT  0 79.515 14.634 79.785 ;
     RECT  0 80.055 14.634 80.325 ;
     RECT  0 80.595 14.634 80.865 ;
     RECT  0 81.135 14.634 81.405 ;
     RECT  0 81.675 14.634 81.945 ;
     RECT  0 82.215 14.634 82.485 ;
     RECT  0 82.755 14.634 83.025 ;
     RECT  0 83.295 14.634 83.565 ;
     RECT  0 83.835 14.634 84.105 ;
     RECT  0 84.375 14.634 84.645 ;
     RECT  0 84.915 14.634 85.185 ;
     RECT  0 85.455 14.634 85.725 ;
     RECT  0 85.995 14.634 86.265 ;
     RECT  0 86.535 14.634 86.805 ;
     RECT  0 87.075 14.634 87.345 ;
     RECT  0 87.615 14.634 87.885 ;
     RECT  0 88.155 14.634 88.425 ;
     RECT  0 88.695 14.634 88.965 ;
     RECT  0 89.235 14.634 89.505 ;
     RECT  0 89.775 14.634 90.045 ;
     RECT  0 90.315 14.634 90.585 ;
     RECT  0 90.855 14.634 91.125 ;
     RECT  0 91.395 14.634 91.665 ;
     RECT  0 91.935 14.634 92.205 ;
     RECT  0 92.475 14.634 92.745 ;
     RECT  0 93.015 14.634 93.285 ;
     RECT  0 93.555 14.634 93.825 ;
     RECT  0 94.095 14.634 94.365 ;
     RECT  0 94.635 14.634 94.905 ;
     RECT  0 95.175 14.634 95.445 ;
     RECT  0 95.715 14.634 95.985 ;
     RECT  0 96.255 14.634 96.525 ;
     RECT  0 96.795 14.634 97.065 ;
     RECT  0 97.335 14.634 97.605 ;
     RECT  0 97.875 14.634 98.145 ;
     RECT  0 98.415 14.634 98.685 ;
     RECT  0 98.955 14.634 99.225 ;
     RECT  0 99.495 14.634 99.765 ;
     RECT  0 100.035 14.634 100.305 ;
     RECT  0 100.575 14.634 100.845 ;
     RECT  0 101.115 14.634 101.385 ;
     RECT  0 101.655 14.634 101.925 ;
     RECT  0 102.195 14.634 102.465 ;
     RECT  0 102.735 14.634 103.005 ;
     RECT  0 103.275 14.634 103.545 ;
     RECT  0 103.815 14.634 104.085 ;
     RECT  0 104.355 14.634 104.625 ;
     RECT  0 104.895 14.634 105.165 ;
     RECT  0 105.435 14.634 105.705 ;
     RECT  0 105.975 14.634 106.245 ;
     RECT  0 106.515 14.634 106.785 ;
     RECT  0 107.055 14.634 107.325 ;
     RECT  0 107.595 14.634 107.865 ;
     RECT  0 108.135 14.634 108.405 ;
     RECT  0 108.675 14.634 108.945 ;
     RECT  0 109.215 14.634 109.485 ;
     RECT  0 109.755 14.634 110.025 ;
     RECT  0 110.295 14.634 110.565 ;
     RECT  0 110.835 14.634 111.105 ;
     RECT  0 111.375 14.634 111.645 ;
     RECT  0 111.915 14.634 112.185 ;
     RECT  0 112.455 14.634 112.725 ;
     RECT  0 112.995 14.634 113.265 ;
     RECT  0 113.535 14.634 113.805 ;
     RECT  0 114.075 14.634 114.345 ;
     RECT  0 114.615 14.634 114.885 ;
     RECT  0 115.155 14.634 115.425 ;
     RECT  0 115.695 14.634 115.965 ;
     RECT  0 116.235 14.634 116.505 ;
     RECT  0 116.775 14.634 117.045 ;
     RECT  0 117.315 14.634 117.585 ;
     RECT  0 117.855 14.634 118.125 ;
     RECT  0 118.395 14.634 118.665 ;
     RECT  0 118.935 14.634 119.205 ;
     RECT  0 119.475 14.634 119.745 ;
     RECT  0 120.015 14.634 120.285 ;
     RECT  0 120.555 14.634 120.825 ;
     RECT  0 121.095 14.634 121.365 ;
     RECT  0 121.635 14.634 121.905 ;
     RECT  0 122.175 14.634 122.445 ;
     RECT  0 122.715 14.634 122.985 ;
     RECT  0 123.255 14.634 123.525 ;
     RECT  0 123.795 14.634 124.065 ;
     RECT  0 124.335 14.634 124.605 ;
     RECT  0 124.875 14.634 125.145 ;
     RECT  0 125.415 14.634 125.685 ;
     RECT  0 125.955 14.634 126.225 ;
     RECT  0 126.495 14.634 126.765 ;
     RECT  0 127.035 14.634 127.305 ;
     RECT  0 127.575 14.634 127.845 ;
     RECT  0 128.115 14.634 128.385 ;
     RECT  0 128.655 14.634 128.925 ;
     RECT  0 129.195 14.634 129.465 ;
     RECT  0 129.735 14.634 130.005 ;
     RECT  0 130.275 14.634 130.545 ;
     RECT  0 130.815 14.634 131.085 ;
     RECT  0 131.355 14.634 131.625 ;
     RECT  0 131.895 14.634 132.165 ;
     RECT  0 132.435 14.634 132.705 ;
     RECT  0 132.975 14.634 133.245 ;
     RECT  0 133.515 14.634 133.785 ;
     RECT  0 134.055 14.634 134.325 ;
     RECT  0 134.595 14.634 134.865 ;
     RECT  0 135.135 14.634 135.405 ;
     RECT  0 135.675 14.634 135.945 ;
     RECT  0 136.215 14.634 136.485 ;
     RECT  0 136.755 14.634 137.025 ;
     RECT  0 137.295 14.634 137.565 ;
     RECT  0 137.835 14.634 138.105 ;
     RECT  0 138.375 14.634 138.645 ;
     RECT  0 138.915 14.634 139.185 ;
     RECT  0 139.455 14.634 139.725 ;
     RECT  0 139.995 14.634 140.265 ;
     RECT  0 140.535 14.634 140.805 ;
     RECT  0 141.075 14.634 141.345 ;
     RECT  0 141.615 14.634 141.75 ;
    LAYER M1 ;
     RECT  0 0.531 14.634 141.759 ;
    LAYER M2 ;
     RECT  0 0.531 14.634 141.759 ;
    LAYER M3 ;
     RECT  6.84 0.619 6.858 0.667 ;
     RECT  7.776 0.187 7.794 0.667 ;
     RECT  0.255 0.523 0.345 0.793 ;
     RECT  5.655 0.523 5.745 0.793 ;
     RECT  11.055 0.523 11.145 0.793 ;
     RECT  5.655 0.793 5.937 1.147 ;
     RECT  6.84 0.667 7.794 1.147 ;
     RECT  9.288 1.147 9.306 1.723 ;
     RECT  5.544 1.147 7.794 1.795 ;
     RECT  5.544 1.795 8.19 1.831 ;
     RECT  9.288 1.723 9.45 1.831 ;
     RECT  5.544 1.831 9.45 1.949 ;
     RECT  5.544 1.949 8.586 2.129 ;
     RECT  9.432 1.949 9.45 2.219 ;
     RECT  9.612 2.335 9.63 2.461 ;
     RECT  9.612 2.461 10.17 2.489 ;
     RECT  9.864 2.489 10.17 2.561 ;
     RECT  5.655 2.129 8.586 3.451 ;
     RECT  9.864 2.561 10.062 3.451 ;
     RECT  9.864 3.451 10.17 3.569 ;
     RECT  5.655 3.451 8.91 3.839 ;
     RECT  9.864 3.569 10.098 3.955 ;
     RECT  5.655 3.839 8.01 4.109 ;
     RECT  8.892 3.839 8.91 4.261 ;
     RECT  9.72 3.955 10.098 4.261 ;
     RECT  8.892 4.261 10.098 4.649 ;
     RECT  8.892 4.649 9.882 4.919 ;
     RECT  8.892 4.919 9.738 5.071 ;
     RECT  7.164 4.109 8.01 5.161 ;
     RECT  8.856 5.071 9.738 5.161 ;
     RECT  7.164 5.161 9.738 5.333 ;
     RECT  7.992 5.333 9.738 5.459 ;
     RECT  7.164 5.333 7.182 6.107 ;
     RECT  8.388 5.459 9.738 6.269 ;
     RECT  8.568 6.269 9.738 7.771 ;
     RECT  8.568 7.771 9.81 8.311 ;
     RECT  11.055 0.793 11.337 8.311 ;
     RECT  6.696 34.843 6.714 34.889 ;
     RECT  6.84 34.897 6.858 34.997 ;
     RECT  8.568 8.311 11.337 39.181 ;
     RECT  8.568 39.181 12.006 39.293 ;
     RECT  8.568 39.293 11.337 40.981 ;
     RECT  8.568 40.981 11.502 41.021 ;
     RECT  8.568 41.021 11.337 41.369 ;
     RECT  8.784 41.369 11.337 43.915 ;
     RECT  8.1 43.915 11.337 44.069 ;
     RECT  13.14 44.635 13.158 44.879 ;
     RECT  12.168 44.971 12.186 45.023 ;
     RECT  7.308 46.219 7.326 46.499 ;
     RECT  7.128 46.891 7.146 46.949 ;
     RECT  8.784 44.069 11.337 49.963 ;
     RECT  8.604 49.963 11.337 50.009 ;
     RECT  8.784 50.009 11.337 50.971 ;
     RECT  8.784 50.971 11.43 51.403 ;
     RECT  12.348 45.031 12.366 51.403 ;
     RECT  7.56 52.507 7.578 52.709 ;
     RECT  8.784 51.403 12.366 52.979 ;
     RECT  8.784 52.979 11.43 54.329 ;
     RECT  12.276 52.979 12.366 54.481 ;
     RECT  8.784 54.329 11.337 55.675 ;
     RECT  12.276 54.481 12.438 55.679 ;
     RECT  8.784 55.675 11.502 55.831 ;
     RECT  12.276 55.679 12.366 55.831 ;
     RECT  8.784 55.831 12.366 55.963 ;
     RECT  8.568 55.963 12.366 56.219 ;
     RECT  8.784 56.219 12.366 57.145 ;
     RECT  8.784 57.145 12.474 57.343 ;
     RECT  8.784 57.343 12.978 57.371 ;
     RECT  8.784 57.371 11.337 58.531 ;
     RECT  12.276 57.371 12.978 58.531 ;
     RECT  7.632 58.795 7.65 58.919 ;
     RECT  8.784 58.531 12.978 59.459 ;
     RECT  8.784 59.459 11.337 60.385 ;
     RECT  12.06 59.459 12.978 60.385 ;
     RECT  7.416 59.071 7.434 60.809 ;
     RECT  8.784 60.385 12.978 60.961 ;
     RECT  8.568 60.961 12.978 62.339 ;
     RECT  8.784 62.339 12.978 66.055 ;
     RECT  8.784 66.055 13.122 66.595 ;
     RECT  8.784 66.595 13.194 69.595 ;
     RECT  8.784 69.595 13.698 69.691 ;
     RECT  8.568 69.691 13.698 69.719 ;
     RECT  8.568 69.719 13.302 69.728 ;
     RECT  7.992 70.219 8.01 70.259 ;
     RECT  8.784 69.728 13.302 70.645 ;
     RECT  8.784 70.645 13.41 70.799 ;
     RECT  8.784 70.799 13.266 71.455 ;
     RECT  14.04 71.275 14.058 71.609 ;
     RECT  8.46 71.455 13.266 71.645 ;
     RECT  8.604 71.645 13.266 71.761 ;
     RECT  8.604 71.761 13.554 71.879 ;
     RECT  8.784 71.879 13.554 72.419 ;
     RECT  8.784 72.419 13.518 73.229 ;
     RECT  8.784 73.229 13.374 73.499 ;
     RECT  7.992 75.883 8.01 75.929 ;
     RECT  8.784 73.499 13.266 77.161 ;
     RECT  7.416 76.081 7.434 77.549 ;
     RECT  8.532 77.161 13.266 82.291 ;
     RECT  8.496 82.291 13.266 82.397 ;
     RECT  8.532 82.397 13.266 83.707 ;
     RECT  7.992 83.707 13.266 83.803 ;
     RECT  7.452 83.803 13.266 84.343 ;
     RECT  6.732 84.343 13.266 84.919 ;
     RECT  6.732 84.919 13.554 85.379 ;
     RECT  7.308 85.379 7.326 85.649 ;
     RECT  8.244 85.379 13.446 87.989 ;
     RECT  8.532 87.989 13.446 88.357 ;
     RECT  8.532 88.357 13.554 88.889 ;
     RECT  8.532 88.889 13.446 90.931 ;
     RECT  8.496 90.931 13.446 91.157 ;
     RECT  8.532 91.157 13.446 91.165 ;
     RECT  8.532 91.165 13.482 91.697 ;
     RECT  8.712 91.697 13.482 96.601 ;
     RECT  8.388 96.601 13.482 104.557 ;
     RECT  8.388 104.557 13.914 112.379 ;
     RECT  8.388 112.379 8.406 118.499 ;
     RECT  9.324 112.379 13.914 123.449 ;
     RECT  9.324 123.449 13.698 123.725 ;
     RECT  9.324 123.725 13.662 125.371 ;
     RECT  9.324 125.371 13.698 125.411 ;
     RECT  9.324 125.411 13.554 126.605 ;
     RECT  9.324 126.605 13.302 126.689 ;
     RECT  9.468 126.689 13.302 129.389 ;
     RECT  9.684 129.389 13.302 139.709 ;
     RECT  10.116 139.709 13.302 139.919 ;
     RECT  10.152 139.919 13.302 140.035 ;
     RECT  10.152 140.035 13.626 140.341 ;
     RECT  10.152 140.341 14.022 141.007 ;
     RECT  10.152 141.007 14.31 141.277 ;
     RECT  10.152 141.277 14.346 141.307 ;
     RECT  10.008 141.307 14.346 141.347 ;
     RECT  0.255 0.793 0.537 141.497 ;
     RECT  5.655 4.109 5.937 141.497 ;
     RECT  0.447 141.497 0.537 141.767 ;
     RECT  5.847 141.497 5.937 141.767 ;
     RECT  10.224 141.347 14.346 141.869 ;
     RECT  10.224 141.869 13.986 141.917 ;
     RECT  10.224 141.917 10.782 141.965 ;
     RECT  11.772 141.917 13.986 141.965 ;
     RECT  12.996 141.965 13.986 142.013 ;
     RECT  13.284 142.013 13.986 142.061 ;
     RECT  10.332 141.965 10.638 142.301 ;
     RECT  10.332 142.301 10.35 142.349 ;
     RECT  11.772 141.965 11.79 142.349 ;
     RECT  13.968 142.061 13.986 142.349 ;
    LAYER M4 ;
     RECT  0.248 0.528 0.352 141.492 ;
     RECT  0.352 0.798 0.44 141.492 ;
     RECT  0.44 0.798 0.544 141.762 ;
     RECT  5.269 0.624 5.461 0.648 ;
     RECT  5.461 0.624 5.489 0.696 ;
     RECT  5.489 0.624 5.509 1.176 ;
     RECT  5.509 0.288 5.648 1.176 ;
     RECT  5.648 0.288 5.749 141.492 ;
     RECT  5.749 0.192 5.84 141.492 ;
     RECT  5.84 0.192 5.944 141.762 ;
     RECT  5.944 0.192 6.301 1.176 ;
     RECT  5.944 34.848 6.851 34.872 ;
     RECT  7.117 46.896 7.297 46.92 ;
     RECT  6.301 0.192 7.373 0.696 ;
     RECT  7.297 46.224 7.427 46.92 ;
     RECT  7.373 0.192 7.523 0.456 ;
     RECT  7.429 52.512 7.589 52.536 ;
     RECT  7.429 58.8 7.661 58.824 ;
     RECT  7.523 0.192 7.805 0.216 ;
     RECT  7.397 83.808 7.937 83.832 ;
     RECT  7.937 70.224 8.021 70.248 ;
     RECT  7.937 75.888 8.021 75.912 ;
     RECT  7.937 83.712 8.021 84.552 ;
     RECT  7.573 43.92 8.129 43.944 ;
     RECT  7.957 82.368 8.525 82.392 ;
     RECT  8.449 71.616 8.533 71.64 ;
     RECT  8.513 55.968 8.597 55.992 ;
     RECT  8.513 69.696 8.597 69.72 ;
     RECT  8.021 83.76 8.627 83.784 ;
     RECT  8.533 49.968 8.633 49.992 ;
     RECT  8.581 87.264 8.665 87.288 ;
     RECT  8.588 78.528 8.675 78.552 ;
     RECT  8.665 87.264 8.705 87.864 ;
     RECT  8.533 80.976 8.849 81 ;
     RECT  8.533 90.672 8.849 90.696 ;
     RECT  9.089 57.12 9.173 57.144 ;
     RECT  9.109 86.688 9.196 86.712 ;
     RECT  9.164 8.352 9.251 8.376 ;
     RECT  9.277 1.152 9.361 1.176 ;
     RECT  9.109 69.984 9.389 70.392 ;
     RECT  8.705 87.696 9.443 87.864 ;
     RECT  9.377 1.728 9.461 1.752 ;
     RECT  9.404 62.304 9.491 62.328 ;
     RECT  9.443 87.84 9.587 87.864 ;
     RECT  9.389 70.368 9.605 70.392 ;
     RECT  8.989 59.76 9.683 59.784 ;
     RECT  9.673 57.024 9.757 57.048 ;
     RECT  9.673 80.4 9.757 80.424 ;
     RECT  9.673 89.664 9.757 89.688 ;
     RECT  9.733 71.856 9.82 71.88 ;
     RECT  9.685 65.568 9.821 65.592 ;
     RECT  9.673 139.68 9.875 139.704 ;
     RECT  9.884 79.056 9.971 79.08 ;
     RECT  9.853 137.328 9.971 137.352 ;
     RECT  9.637 83.52 10.172 83.544 ;
     RECT  9.997 141.312 10.213 141.336 ;
     RECT  10.213 141.312 10.249 141.96 ;
     RECT  5.944 76.992 10.261 77.016 ;
     RECT  10.172 83.184 10.261 83.544 ;
     RECT  10.249 140.784 10.321 141.96 ;
     RECT  10.249 53.088 10.393 53.112 ;
     RECT  9.961 129.36 10.429 129.384 ;
     RECT  10.321 140.784 10.547 142.344 ;
     RECT  10.547 140.784 10.649 142.296 ;
     RECT  10.649 140.784 10.717 142.248 ;
     RECT  9.685 54.192 10.741 54.216 ;
     RECT  10.249 67.296 10.825 67.32 ;
     RECT  10.124 89.856 10.837 89.88 ;
     RECT  10.717 140.208 10.837 142.248 ;
     RECT  10.249 68.448 10.933 68.472 ;
     RECT  10.609 127.056 10.933 127.08 ;
     RECT  10.825 36.864 11.048 36.888 ;
     RECT  10.844 38.016 11.048 38.04 ;
     RECT  9.853 46.08 11.048 46.104 ;
     RECT  10.933 51.504 11.048 51.528 ;
     RECT  10.393 52.944 11.048 53.112 ;
     RECT  10.741 54.096 11.048 54.216 ;
     RECT  9.961 56.208 11.048 56.232 ;
     RECT  10.501 57.504 11.048 57.528 ;
     RECT  10.837 58.608 11.048 58.632 ;
     RECT  10.249 63.312 11.048 63.336 ;
     RECT  10.825 66.768 11.048 67.32 ;
     RECT  10.933 68.448 11.048 68.952 ;
     RECT  10.933 70.08 11.048 70.104 ;
     RECT  10.933 72.768 11.048 72.792 ;
     RECT  10.597 73.92 11.048 73.944 ;
     RECT  10.261 76.992 11.048 77.064 ;
     RECT  10.597 79.392 11.048 79.416 ;
     RECT  10.261 82.944 11.048 83.544 ;
     RECT  10.837 89.568 11.048 89.88 ;
     RECT  10.028 92.4 11.048 92.424 ;
     RECT  10.933 94.56 11.048 94.584 ;
     RECT  10.028 104.784 11.048 104.808 ;
     RECT  10.105 106.08 11.048 106.104 ;
     RECT  10.501 125.376 11.048 125.4 ;
     RECT  10.933 127.056 11.048 127.656 ;
     RECT  10.429 129.36 11.048 130.008 ;
     RECT  10.837 140.016 11.048 142.248 ;
     RECT  11.048 0.528 11.152 142.248 ;
     RECT  11.152 0.798 11.344 142.248 ;
     RECT  11.344 140.016 11.405 142.248 ;
     RECT  11.344 57.024 11.477 57.048 ;
     RECT  11.344 61.248 11.485 61.272 ;
     RECT  11.344 63.504 11.513 63.528 ;
     RECT  11.344 40.992 11.548 41.016 ;
     RECT  11.344 55.68 11.555 55.704 ;
     RECT  11.344 66.336 11.555 66.36 ;
     RECT  11.344 105.312 11.555 105.336 ;
     RECT  11.344 127.68 11.603 128.232 ;
     RECT  11.344 138.528 11.699 138.552 ;
     RECT  11.405 140.784 11.717 142.248 ;
     RECT  11.344 86.352 11.74 86.376 ;
     RECT  11.344 76.992 11.765 77.016 ;
     RECT  11.344 79.392 11.765 79.416 ;
     RECT  11.717 140.784 11.801 142.344 ;
     RECT  11.603 128.208 11.881 128.232 ;
     RECT  11.344 129.36 11.891 130.344 ;
     RECT  11.344 132.24 11.987 132.264 ;
     RECT  11.344 39.264 12.061 39.288 ;
     RECT  11.344 62.4 12.061 62.424 ;
     RECT  11.801 140.784 12.083 142.248 ;
     RECT  11.344 68.88 12.131 68.904 ;
     RECT  11.344 44.976 12.197 45 ;
     RECT  11.344 70.8 12.275 71.016 ;
     RECT  11.891 129.36 12.313 129.384 ;
     RECT  11.344 120.24 12.323 120.264 ;
     RECT  12.083 141.312 12.629 142.248 ;
     RECT  12.517 86.112 12.665 86.136 ;
     RECT  12.572 125.424 12.697 125.448 ;
     RECT  12.661 69.696 12.748 69.72 ;
     RECT  12.517 140.256 12.809 140.28 ;
     RECT  12.764 72.72 12.851 72.744 ;
     RECT  12.661 122.544 13.043 122.568 ;
     RECT  12.697 125.424 13.091 125.784 ;
     RECT  12.517 70.752 13.097 70.776 ;
     RECT  12.553 139.104 13.139 139.128 ;
     RECT  13.085 44.64 13.169 44.664 ;
     RECT  13.057 140.208 13.427 140.232 ;
     RECT  13.201 126.576 13.619 126.6 ;
     RECT  13.628 125.376 13.715 125.4 ;
     RECT  13.669 69.6 13.753 69.624 ;
     RECT  12.629 141.936 13.765 142.248 ;
     RECT  13.669 123.696 13.907 123.72 ;
     RECT  13.765 141.552 13.957 142.248 ;
     RECT  13.957 141.552 14.041 142.344 ;
     RECT  13.669 71.28 14.069 71.304 ;
     RECT  14.041 141.552 14.508 141.864 ;
    LAYER M5 ;
     RECT  5.184 0.144 9.432 0.235 ;
     RECT  5.28 0.235 9.432 0.619 ;
     RECT  5.28 0.619 8.184 0.659 ;
     RECT  5.472 0.659 8.184 0.707 ;
     RECT  0.24 0.517 0.36 0.787 ;
     RECT  11.04 0.517 11.16 0.787 ;
     RECT  5.52 0.707 8.184 0.811 ;
     RECT  5.52 0.811 6.264 1.187 ;
     RECT  9.312 0.619 9.432 1.187 ;
     RECT  9.408 1.187 9.432 1.763 ;
     RECT  9.216 8.341 9.24 8.427 ;
     RECT  5.64 1.187 5.952 34.799 ;
     RECT  7.584 0.811 7.608 34.799 ;
     RECT  5.64 34.799 7.608 34.883 ;
     RECT  11.04 0.787 11.352 36.853 ;
     RECT  10.848 36.853 11.352 36.937 ;
     RECT  11.04 36.937 11.352 37.971 ;
     RECT  10.896 37.971 11.352 38.059 ;
     RECT  11.04 38.059 11.352 39.253 ;
     RECT  11.04 39.253 12.024 39.339 ;
     RECT  11.04 39.339 11.352 40.981 ;
     RECT  11.04 40.981 11.496 41.067 ;
     RECT  7.584 34.883 7.608 43.955 ;
     RECT  13.104 44.591 13.128 44.675 ;
     RECT  11.04 41.067 11.352 44.965 ;
     RECT  11.04 44.965 12.024 45.227 ;
     RECT  11.04 45.227 11.352 46.069 ;
     RECT  10.224 46.069 11.352 46.153 ;
     RECT  7.392 46.175 7.416 46.931 ;
     RECT  8.544 49.957 8.568 50.041 ;
     RECT  11.04 46.153 11.352 51.475 ;
     RECT  10.944 51.475 11.352 51.563 ;
     RECT  7.44 52.463 7.464 52.547 ;
     RECT  11.04 51.563 11.352 52.895 ;
     RECT  10.8 52.895 11.352 53.039 ;
     RECT  10.272 53.039 11.352 53.123 ;
     RECT  10.752 53.123 11.352 54.157 ;
     RECT  9.696 54.133 9.72 54.227 ;
     RECT  11.04 54.157 11.352 55.605 ;
     RECT  11.04 55.605 11.544 55.715 ;
     RECT  8.544 55.919 8.568 56.003 ;
     RECT  11.04 55.715 11.352 56.159 ;
     RECT  10.224 56.159 11.352 56.243 ;
     RECT  11.04 56.243 11.352 57.013 ;
     RECT  9.696 57.013 9.72 57.071 ;
     RECT  9.12 57.071 9.72 57.097 ;
     RECT  11.04 57.013 11.448 57.097 ;
     RECT  9.12 57.097 9.144 57.155 ;
     RECT  11.04 57.097 11.352 57.493 ;
     RECT  10.752 57.493 11.352 57.579 ;
     RECT  11.04 57.579 11.352 58.549 ;
     RECT  10.848 58.549 11.352 58.643 ;
     RECT  7.44 58.741 7.464 58.835 ;
     RECT  9.648 59.731 9.672 59.819 ;
     RECT  11.04 58.643 11.352 61.237 ;
     RECT  11.04 61.237 11.448 61.419 ;
     RECT  9.456 62.293 9.48 62.379 ;
     RECT  11.04 61.419 11.352 62.389 ;
     RECT  11.04 62.389 12.024 62.473 ;
     RECT  11.04 62.473 11.352 63.263 ;
     RECT  10.272 63.263 11.352 63.347 ;
     RECT  11.04 63.347 11.352 63.455 ;
     RECT  11.04 63.455 11.448 63.539 ;
     RECT  9.696 65.519 9.72 65.603 ;
     RECT  11.04 63.539 11.352 66.325 ;
     RECT  11.04 66.325 11.544 66.411 ;
     RECT  11.04 66.411 11.352 66.719 ;
     RECT  10.848 66.719 11.352 67.247 ;
     RECT  10.272 67.247 11.352 67.331 ;
     RECT  11.04 67.331 11.352 68.399 ;
     RECT  10.272 68.399 11.352 68.483 ;
     RECT  10.944 68.483 11.352 68.853 ;
     RECT  10.944 68.853 12.12 68.941 ;
     RECT  10.944 68.941 11.352 68.971 ;
     RECT  13.68 69.551 13.704 69.635 ;
     RECT  12.672 69.621 12.696 69.731 ;
     RECT  8.544 69.685 8.568 69.769 ;
     RECT  11.04 68.971 11.352 70.069 ;
     RECT  10.944 70.069 11.352 70.153 ;
     RECT  7.968 70.175 7.992 70.259 ;
     RECT  9.12 69.973 9.144 70.403 ;
     RECT  11.04 70.153 11.352 70.751 ;
     RECT  12.528 70.703 12.552 70.751 ;
     RECT  11.04 70.751 12.552 70.787 ;
     RECT  11.04 70.787 12.264 71.083 ;
     RECT  13.68 71.029 13.704 71.315 ;
     RECT  8.496 71.605 8.52 71.689 ;
     RECT  9.744 71.605 9.768 71.891 ;
     RECT  11.04 71.083 11.352 72.757 ;
     RECT  12.816 72.693 12.84 72.781 ;
     RECT  10.944 72.757 11.352 73.875 ;
     RECT  10.608 73.875 11.352 73.963 ;
     RECT  7.968 75.877 7.992 75.961 ;
     RECT  11.04 73.963 11.352 76.947 ;
     RECT  5.64 34.883 5.952 76.981 ;
     RECT  10.368 76.947 11.352 76.981 ;
     RECT  5.64 76.981 6.936 77.065 ;
     RECT  10.176 76.981 11.448 77.065 ;
     RECT  10.176 77.065 11.352 77.099 ;
     RECT  8.64 78.483 8.664 78.571 ;
     RECT  9.936 79.029 9.96 79.117 ;
     RECT  11.04 77.099 11.352 79.285 ;
     RECT  10.608 79.285 11.352 79.343 ;
     RECT  10.608 79.343 11.448 79.427 ;
     RECT  10.704 79.427 11.352 79.437 ;
     RECT  9.696 80.351 9.72 80.435 ;
     RECT  8.544 80.927 8.568 81.011 ;
     RECT  7.968 82.357 7.992 82.441 ;
     RECT  11.04 79.437 11.352 82.933 ;
     RECT  10.272 82.933 11.352 83.155 ;
     RECT  10.224 83.155 11.352 83.563 ;
     RECT  8.592 83.253 8.616 83.701 ;
     RECT  7.968 83.701 8.616 83.759 ;
     RECT  7.44 83.759 8.616 83.795 ;
     RECT  7.44 83.795 7.992 83.843 ;
     RECT  7.968 83.843 7.992 84.601 ;
     RECT  12.528 86.063 12.552 86.147 ;
     RECT  11.04 83.563 11.352 86.303 ;
     RECT  11.04 86.303 11.688 86.443 ;
     RECT  9.12 86.639 9.144 86.723 ;
     RECT  8.592 87.215 8.616 87.299 ;
     RECT  9.408 87.685 9.432 87.797 ;
     RECT  9.408 87.797 9.576 87.851 ;
     RECT  9.552 87.851 9.576 87.885 ;
     RECT  11.04 86.443 11.352 89.519 ;
     RECT  9.696 89.653 9.72 89.737 ;
     RECT  10.848 89.519 11.352 89.811 ;
     RECT  10.176 89.811 11.352 89.899 ;
     RECT  8.544 90.613 8.568 90.707 ;
     RECT  11.04 89.899 11.352 92.341 ;
     RECT  10.08 92.341 11.352 92.435 ;
     RECT  11.04 92.435 11.352 94.549 ;
     RECT  10.944 94.549 11.352 94.635 ;
     RECT  11.04 94.635 11.352 104.757 ;
     RECT  10.08 104.757 11.352 104.845 ;
     RECT  11.04 104.845 11.352 105.269 ;
     RECT  11.04 105.269 11.544 105.357 ;
     RECT  11.04 105.357 11.352 106.031 ;
     RECT  10.224 106.031 11.352 106.115 ;
     RECT  11.04 106.115 11.352 120.229 ;
     RECT  11.04 120.229 12.312 122.533 ;
     RECT  11.04 122.533 13.032 123.685 ;
     RECT  11.04 123.685 13.896 125.365 ;
     RECT  10.512 125.365 13.896 129.349 ;
     RECT  10.032 129.349 13.896 137.317 ;
     RECT  9.936 137.317 13.896 139.669 ;
     RECT  0.24 0.787 0.552 141.684 ;
     RECT  5.64 77.065 5.952 141.684 ;
     RECT  0.432 141.684 0.552 141.773 ;
     RECT  5.832 141.684 5.952 141.773 ;
     RECT  9.84 139.669 13.896 142.309 ;
     RECT  9.84 142.309 13.992 142.48 ;
    LAYER M6 ;
     RECT  0 0.996 5.154 1.86 ;
     RECT  0 76.596 5.173 77.46 ;
     RECT  0 81.996 5.365 82.86 ;
     RECT  5.365 81.996 5.557 83.744 ;
     RECT  5.557 81.996 6.069 83.808 ;
     RECT  6.133 69.696 6.709 69.728 ;
     RECT  0 71.196 6.709 72.06 ;
     RECT  0 33.396 6.805 34.26 ;
     RECT  5.173 75.904 6.901 77.46 ;
     RECT  6.901 74.688 7.083 77.46 ;
     RECT  6.069 81.996 7.093 84.576 ;
     RECT  0 87.396 7.157 88.26 ;
     RECT  0 44.196 7.381 45.06 ;
     RECT  7.221 52.48 7.475 52.512 ;
     RECT  7.029 58.752 7.475 58.784 ;
     RECT  7.093 80.96 7.733 84.576 ;
     RECT  7.285 90.624 7.797 90.656 ;
     RECT  7.381 44.196 7.915 46.88 ;
     RECT  6.805 33.396 7.979 34.848 ;
     RECT  7.083 75.904 8.003 77.46 ;
     RECT  7.733 80.384 8.003 84.576 ;
     RECT  7.915 46.848 8.107 46.88 ;
     RECT  0 65.796 8.245 66.66 ;
     RECT  0 54.996 8.437 55.86 ;
     RECT  6.709 69.696 8.579 72.06 ;
     RECT  8.003 80.384 8.579 83.744 ;
     RECT  7.797 89.664 8.579 90.656 ;
     RECT  8.003 76.596 8.61 77.46 ;
     RECT  8.245 65.536 8.629 66.66 ;
     RECT  8.579 81.996 8.638 83.744 ;
     RECT  8.61 76.596 8.683 78.56 ;
     RECT  8.638 81.996 8.683 83.296 ;
     RECT  8.437 54.996 8.693 57.056 ;
     RECT  0 60.396 8.757 61.26 ;
     RECT  8.693 54.144 9.013 57.056 ;
     RECT  9.013 54.144 9.077 57.12 ;
     RECT  8.629 65.536 9.141 67.296 ;
     RECT  9.077 53.056 9.155 57.12 ;
     RECT  8.579 70.016 9.155 72.06 ;
     RECT  7.157 86.656 9.155 88.26 ;
     RECT  0 6.396 9.186 7.26 ;
     RECT  9.186 6.396 9.259 8.416 ;
     RECT  8.757 60.396 9.269 61.408 ;
     RECT  7.989 63.296 9.269 63.328 ;
     RECT  9.155 87.396 9.397 88.26 ;
     RECT  8.579 89.664 9.397 89.696 ;
     RECT  5.154 0.192 9.451 1.86 ;
     RECT  9.269 60.396 9.637 63.328 ;
     RECT  9.141 65.536 9.731 68.448 ;
     RECT  8.579 80.384 9.731 80.416 ;
     RECT  0 92.796 10.069 93.66 ;
     RECT  0 103.596 10.069 104.46 ;
     RECT  10.069 92.352 10.101 93.66 ;
     RECT  10.101 92.352 10.155 94.624 ;
     RECT  10.069 103.596 10.155 104.8 ;
     RECT  9.397 87.396 10.165 89.696 ;
     RECT  7.915 44.196 10.213 45.06 ;
     RECT  8.683 81.996 10.213 82.976 ;
     RECT  9.637 59.776 10.293 63.328 ;
     RECT  9.731 65.796 10.307 68.448 ;
     RECT  10.293 58.56 10.347 63.52 ;
     RECT  9.925 79.04 10.597 79.072 ;
     RECT  10.597 73.92 10.667 73.952 ;
     RECT  10.597 79.04 10.667 79.392 ;
     RECT  10.667 79.296 10.671 79.392 ;
     RECT  10.229 86.08 10.677 86.112 ;
     RECT  10.165 87.396 10.677 89.888 ;
     RECT  10.213 81.996 10.731 83.552 ;
     RECT  9.155 53.056 10.741 57.056 ;
     RECT  10.347 58.56 10.741 58.592 ;
     RECT  10.741 53.056 10.789 58.592 ;
     RECT  10.789 52.928 10.795 58.592 ;
     RECT  10.795 54.996 10.81 58.592 ;
     RECT  9.205 36.864 10.869 36.896 ;
     RECT  0 38.796 10.869 39.66 ;
     RECT  9.155 71.196 10.869 72.06 ;
     RECT  10.81 58.56 10.883 58.592 ;
     RECT  10.677 86.08 10.883 89.888 ;
     RECT  0 49.596 10.933 50.46 ;
     RECT  10.869 68.928 10.933 69.728 ;
     RECT  10.869 71.196 10.933 72.928 ;
     RECT  10.869 36.864 10.942 39.66 ;
     RECT  10.155 92.796 10.979 94.624 ;
     RECT  10.795 52.928 11.051 52.96 ;
     RECT  10.307 65.796 11.115 66.912 ;
     RECT  10.213 106.048 11.115 106.08 ;
     RECT  10.933 49.596 11.243 51.552 ;
     RECT  0 141.396 11.253 141.684 ;
     RECT  10.933 68.928 11.307 72.928 ;
     RECT  9.451 0.996 11.352 1.86 ;
     RECT  9.259 6.396 11.352 7.26 ;
     RECT  0 11.796 11.352 12.66 ;
     RECT  0 17.196 11.352 18.06 ;
     RECT  0 22.596 11.352 23.46 ;
     RECT  0 27.996 11.352 28.86 ;
     RECT  7.979 33.396 11.352 34.26 ;
     RECT  10.942 38.796 11.352 39.66 ;
     RECT  11.243 49.596 11.352 50.46 ;
     RECT  11.115 65.796 11.352 66.66 ;
     RECT  8.683 76.596 11.352 77.46 ;
     RECT  10.731 81.996 11.352 82.86 ;
     RECT  10.883 86.08 11.352 88.26 ;
     RECT  10.979 92.796 11.352 93.66 ;
     RECT  0 98.196 11.352 99.06 ;
     RECT  10.155 103.596 11.352 104.46 ;
     RECT  0 108.996 11.352 109.86 ;
     RECT  0 114.396 11.352 115.26 ;
     RECT  0 119.796 11.352 120.66 ;
     RECT  0 125.196 11.352 126.06 ;
     RECT  0 130.596 11.352 131.46 ;
     RECT  0 135.996 11.352 136.86 ;
     RECT  10.942 36.864 11.371 36.896 ;
     RECT  10.213 44.196 11.371 46.112 ;
     RECT  10.81 54.996 11.459 57.056 ;
     RECT  10.347 60.396 11.459 63.52 ;
     RECT  11.352 76.596 11.459 77.024 ;
     RECT  10.671 79.36 11.459 79.392 ;
     RECT  11.253 141.396 11.509 141.792 ;
     RECT  11.445 41.024 11.518 41.056 ;
     RECT  11.459 54.996 11.563 56.224 ;
     RECT  10.883 89.856 11.563 89.888 ;
     RECT  11.49 105.28 11.563 105.312 ;
     RECT  11.352 86.08 11.699 87.684 ;
     RECT  11.352 0.996 11.944 1.284 ;
     RECT  11.352 6.396 11.944 6.684 ;
     RECT  11.352 11.796 11.944 12.084 ;
     RECT  11.352 17.196 11.944 17.484 ;
     RECT  11.352 22.596 11.944 22.884 ;
     RECT  11.352 27.996 11.944 28.284 ;
     RECT  11.352 33.396 11.944 33.684 ;
     RECT  11.352 38.796 11.944 39.328 ;
     RECT  11.371 44.196 11.944 45.216 ;
     RECT  11.352 49.596 11.944 49.884 ;
     RECT  11.563 54.996 11.944 55.284 ;
     RECT  11.459 60.396 11.944 60.684 ;
     RECT  11.352 65.796 11.944 66.4 ;
     RECT  11.459 76.596 11.944 76.884 ;
     RECT  11.352 81.996 11.944 82.284 ;
     RECT  11.699 87.396 11.944 87.684 ;
     RECT  11.352 92.796 11.944 93.084 ;
     RECT  11.352 98.196 11.944 98.484 ;
     RECT  11.352 103.596 11.944 103.884 ;
     RECT  11.352 108.996 11.944 109.284 ;
     RECT  11.352 114.396 11.944 114.684 ;
     RECT  11.352 119.796 11.944 120.084 ;
     RECT  11.352 125.196 11.944 125.484 ;
     RECT  11.352 130.596 11.944 130.884 ;
     RECT  11.352 135.996 11.944 136.284 ;
     RECT  11.509 140.224 11.944 141.792 ;
     RECT  11.944 39.296 12.035 39.328 ;
     RECT  11.944 44.608 12.035 45.216 ;
     RECT  11.459 62.4 12.035 62.432 ;
     RECT  11.307 68.928 12.066 72.736 ;
     RECT  11.944 66.368 12.139 66.4 ;
     RECT  12.066 68.864 12.139 72.736 ;
     RECT  12.139 69.568 12.563 71.072 ;
     RECT  11.699 86.08 12.563 86.112 ;
     RECT  11.944 140.224 12.563 140.256 ;
     RECT  12.563 69.568 12.707 69.664 ;
     RECT  12.139 72.704 12.851 72.736 ;
     RECT  12.035 44.608 13.139 44.64 ;
     RECT  12.707 69.568 13.715 69.6 ;
     RECT  12.563 71.04 13.715 71.072 ;
     RECT  11.944 141.76 13.811 141.792 ;
    LAYER M7 ;
     RECT  5.184 0.181 7.776 0.245 ;
     RECT  9.408 0.181 9.44 0.245 ;
     RECT  11.656 0.531 11.944 36.853 ;
     RECT  11.328 36.853 11.944 38.005 ;
     RECT  10.88 38.005 11.944 54.069 ;
     RECT  5.184 0.245 9.44 58.549 ;
     RECT  10.752 54.069 11.944 58.549 ;
     RECT  5.184 58.549 11.944 63.531 ;
     RECT  10.88 63.531 11.944 66.357 ;
     RECT  10.88 66.357 12.128 66.923 ;
     RECT  5.184 63.531 9.44 67.307 ;
     RECT  9.152 67.307 9.44 68.459 ;
     RECT  11.072 66.923 12.128 68.917 ;
     RECT  10.944 68.917 12.128 69.685 ;
     RECT  10.88 69.685 12.128 71.659 ;
     RECT  9.408 68.459 9.44 73.909 ;
     RECT  10.88 71.659 11.944 73.909 ;
     RECT  5.184 67.307 7.84 75.947 ;
     RECT  9.408 73.909 11.944 77.099 ;
     RECT  5.376 75.947 7.84 78.517 ;
     RECT  10.624 77.099 11.944 79.339 ;
     RECT  10.688 79.339 11.944 83.189 ;
     RECT  5.376 78.517 8.672 83.307 ;
     RECT  5.376 83.307 8.608 83.755 ;
     RECT  5.568 83.755 8.608 83.819 ;
     RECT  6.08 83.819 8.608 84.587 ;
     RECT  10.24 83.189 11.944 86.123 ;
     RECT  10.688 86.123 11.944 86.39 ;
     RECT  6.256 84.587 8.608 87.275 ;
     RECT  10.752 86.39 11.944 87.797 ;
     RECT  9.408 87.797 11.944 89.579 ;
     RECT  6.256 87.275 7.84 89.707 ;
     RECT  6.256 89.707 7.328 90.667 ;
     RECT  10.112 89.579 11.944 104.811 ;
     RECT  11.072 104.811 11.944 106.091 ;
     RECT  0.856 0.531 1.144 141.759 ;
     RECT  6.256 90.667 6.544 141.759 ;
     RECT  11.264 106.091 11.944 141.759 ;
     RECT  11.264 141.759 11.296 141.803 ;
  END
END hfd_stn_r2
END LIBRARY
